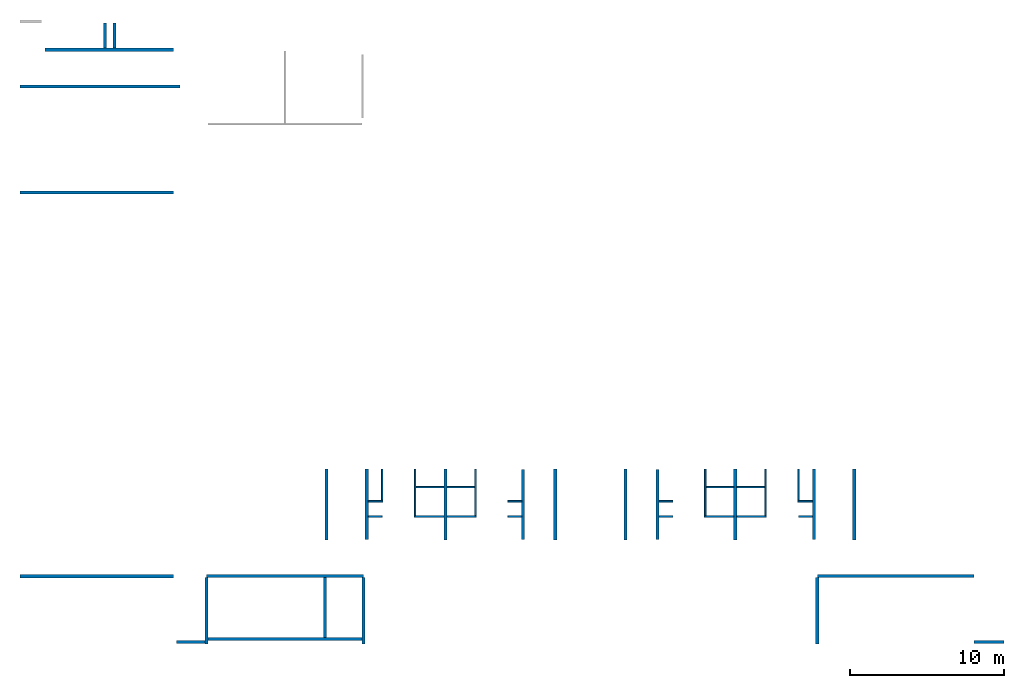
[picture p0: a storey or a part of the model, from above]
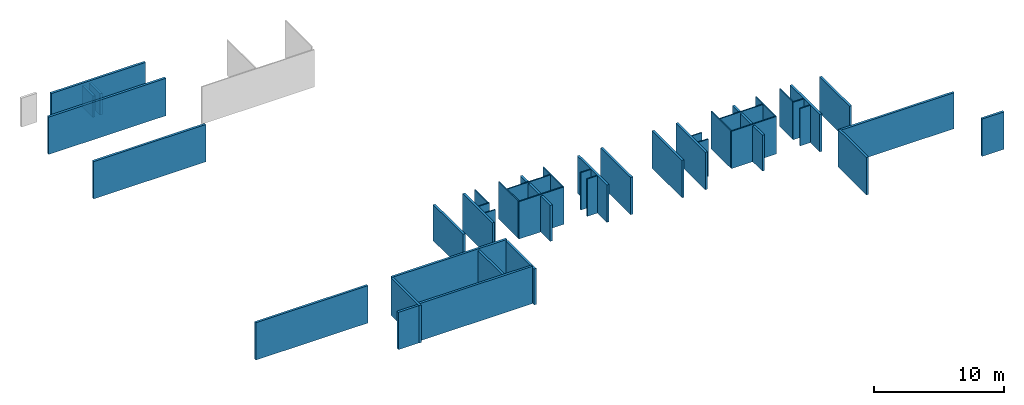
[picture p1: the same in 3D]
Properties of the parts of a building model (IFC2X3), part 1 of 3

# File
Description: ViewDefinition [CoordinationView_V2.0]
File name: Project Number
Time: 2020-09-23T12:17:25
Written by: The EXPRESS Data Manager Version 5.02.0100.07 : 28 Aug 2013
Made in: 21.0.0.383 - Exporter 21.0.0.383 - Alternate UI 21.0.0.383
Comment: STEP Physical File produced by: The EXPRESS Data Manager Version 5.02.0100.07 : 28 Aug 2013 * Module: EDMstepFileFactory/EDMstandAlone * Creation date: Wed Sep 23 12:17:25 2020 * Host: DESKTOP-DG8BND5 * Database: C:\Users\X\AppData\Local\Temp\ed47b6ea-077b-444b-8792-7ce0966b8367\d63a7d49-ede5-44a4-a1c5-d3353abeedfa\ifc * Database version: 5507 * Database creation date: Wed Sep 23 12:11:32 2020 * Schema: IFC2X3 * Model: DataRepository.ifc * Model creation date: Wed Sep 23 12:11:33 2020 * Header model: DataRepository.ifc_HeaderModel * Header model creation date: Wed Sep 23 12:11:33 2020 * EDMuser: sdai-user * EDMgroup: sdai-group * License ID and type: 5605 : Permanent license. Expiry date: * EDMstepFileFactory options: 020000

# IfcProject, Project Number
LongName: Project Name; Phase: Project Status

# IfcSite, Default
RefLatitude: 48, 41, 46, 352233; RefLongitude: 6, 11, 34, 519615; RefElevation: 0 mm
Pset_ProductRequirements - Category: Project Information
Other - Category: Project Information; Client Name: Owner; Project Address: Enter address here; Project Issue Date: Issue Date; Project Name: Project Name; Project Number: Project Number; Project Status: Project Status

# IfcBuilding
Pset_BuildingCommon - NumberOfStoreys: 4
Pset_ProductRequirements - Category: Project Information
Other - Category: Project Information; Client Name: Owner; Project Address: Enter address here; Project Issue Date: Issue Date; Project Name: Project Name; Project Number: Project Number; Project Status: Project Status

# IfcBuildingStorey: Level:Circle Head - Project Datum (4)
Other(Type) - Category: Levels; Family Name: Level
Identity Data(Type) - Type Name: Circle Head - Project Datum
Graphics(Type) - Color: 0; Line Pattern: Centre; Line Weight: 1; Symbol: Anno_Level_Head_Circle: Standard; Symbol at End 1 Default: yes; Symbol at End 2 Default: no
Constraints(Type) - Elevation Base: Project Base Point
Pset_ProductRequirements - Category: Levels
Dimensions - Computation Height: 0 mm
Identity Data - Building Story: yes
Other - Category: Levels; Family: Level: Circle Head - Project Datum; Family and Type: Level: Circle Head - Project Datum; Type: Level: Circle Head - Project Datum; Type Id: Level: Circle Head - Project Datum
Name | LongName = Pset_AirSideSystemInformation, Name = Pset_ProductRequirements, Name = Identity Data, Name | Elevation (mm) = Constraints, Elevation (mm) | Structural
R-1 | R-1 | -3500 | yes
RDC | RDC | 0 | no
R+1 | R+1 | 3660 | no
R+2 | R+2 | 7320 | no

# IfcBuildingElementProxy: Cloisin vitre bois vitrage P-F 3-4H 498x296:Cloisin vitre bois vitrage P-F 3-4H 498x296 (22)
In: RDC
Type - Material: Glass
Type - Constraints - Default Elevation: 0 mm
Type - Identity Data - Type Name: Cloisin vitre bois vitrage P-F 3-4H 498x296
Type - Other - Category: Generic Models; Family Name: Cloisin vitre bois vitrage P-F 3-4H 498x296
Type - Pset_BuildingElementProxyCommon - Reference: Cloisin vitre bois vitrage P-F 3-4H 498x296
Type - Pset_ProductRequirements - Category: Generic Models
Type - Pset_QuantityTakeOff - Reference: Cloisin vitre bois vitrage P-F 3-4H 498x296
Material: Glass, Softwood, Finish Black
Pset_BuildingElementProxyCommon - sets with these values: 2
Constraints - Elevation from Level: 0 mm; Level: Level: RDC; Moves With Nearby Elements: no; Offset from Host: 0 mm; Host: Floor : PlancherChauffant130Rouge
Dimensions - Area: 18.2039 m2; Volume: 0.149386 m3
Other - Family: Cloisin vitre bois vitrage P-F 3-4H 498x296: Cloisin vitre bois vitrage P-F 3-4H 498x296; Family and Type: Cloisin vitre bois vitrage P-F 3-4H 498x296: Cloisin vitre bois vitrage P-F 3-4H 498x296; Type: Cloisin vitre bois vitrage P-F 3-4H 498x296: Cloisin vitre bois vitrage P-F 3-4H 498x296; Type Id: Cloisin vitre bois vitrage P-F 3-4H 498x296: Cloisin vitre bois vitrage P-F 3-4H 498x296
Phasing - Phase Created: Existing
Name (Cloisin vitre bois vitrage P-F 3-4H 498x296:Cloisin vitre bois vitrage P-F 3-4H 498x296:...)
486566 | Pset_ProvisionForVoid - Width: 30 mm; Height: 1830 mm; Depth: 30 mm
486831
486865
486875
486885
486895
486905
486915
486925
486935
486945
486983 | Pset_ProvisionForVoid - Width: 30 mm; Height: 1830 mm; Depth: 30 mm
486985
486987
486989
486991
486993
486995
486997
486999
487001
487003

# IfcBuildingElementProxy: FENETRE.dwg:Fenetre ext 296+70 (124)
Type - Material: PVC, Flexible
Type - Constraints - Default Elevation: 0 mm
Type - Dimensions - Facadecover top: 700 mm
Type - Identity Data - Type Name: Fenetre ext 296+70
Type - Other - Category: Generic Models; Family Name: FENETRE.dwg
Type - Pset_BuildingElementProxyCommon - Reference: Fenetre ext 296+70
Type - Pset_ProductRequirements - Category: Generic Models
Type - Pset_QuantityTakeOff - Reference: Fenetre ext 296+70
Material: PVC, Flexible, Glass
Pset_BuildingElementProxyCommon - sets with these values: 2
Constraints - Elevation from Level: 0 mm; Moves With Nearby Elements: no; Offset from Host: 0 mm
Dimensions - Area: 13.0772 m2; Volume: 0.605172 m3
Other - Family: FENETRE.dwg: Fenetre ext 296+70; Family and Type: FENETRE.dwg: Fenetre ext 296+70; Type: FENETRE.dwg: Fenetre ext 296+70; Type Id: FENETRE.dwg: Fenetre ext 296+70
Phasing - Phase Created: Existing
Name (FENETRE.dwg:Fenetre ext 296+70:...) | In | Host | Level | Group
481956 | RDC | Level : RDC | Level: RDC | Model Group:Array Group 5:484323 | Pset_ProvisionForVoid - Width: 50 mm; Height: 1335 mm; Depth: 50 mm
484326 | RDC | Level : RDC | Level: RDC | Model Group:Array Group 5:484327
484344 | RDC | Level : RDC | Level: RDC | Model Group:Array Group 5:484345
484347 | RDC | Level : RDC | Level: RDC | Model Group:Array Group 5:484348
484350 | RDC | Level : RDC | Level: RDC | Model Group:Array Group 5:484351
484353 | RDC | Level : RDC | Level: RDC | Model Group:Array Group 5:484354
484356 | RDC | Level : RDC | Level: RDC | Model Group:Array Group 5:484357
484359 | RDC | Level : RDC | Level: RDC | Model Group:Array Group 5:484360
484362 | RDC | Level : RDC | Level: RDC | Model Group:Array Group 5:484363
484365 | RDC | Level : RDC | Level: RDC | Model Group:Array Group 5:484366
484368 | RDC | Level : RDC | Level: RDC | Model Group:Array Group 5:484369
484371 | RDC | Level : RDC | Level: RDC | Model Group:Array Group 5:484372
484374 | RDC | Level : RDC | Level: RDC | Model Group:Array Group 5:484375
484377 | RDC | Level : RDC | Level: RDC | Model Group:Array Group 5:484378
484380 | RDC | Level : RDC | Level: RDC | Model Group:Array Group 5:484381
484383 | RDC | Level : RDC | Level: RDC | Model Group:Array Group 5:484384
484386 | RDC | Level : RDC | Level: RDC | Model Group:Array Group 5:484387
484389 | R+1 | Level : R+1 | Level: R+1 | Model Group:Array Group 5:484390
484391 | R+1 | Level : R+1 | Level: R+1 | Model Group:Array Group 5:484392
484393 | R+1 | Level : R+1 | Level: R+1 | Model Group:Array Group 5:484394
484395 | R+1 | Level : R+1 | Level: R+1 | Model Group:Array Group 5:484396
484397 | R+1 | Level : R+1 | Level: R+1 | Model Group:Array Group 5:484398
484399 | R+1 | Level : R+1 | Level: R+1 | Model Group:Array Group 5:484400
484401 | R+1 | Level : R+1 | Level: R+1 | Model Group:Array Group 5:484402
484403 | R+1 | Level : R+1 | Level: R+1 | Model Group:Array Group 5:484404
484405 | R+1 | Level : R+1 | Level: R+1 | Model Group:Array Group 5:484406
484407 | R+1 | Level : R+1 | Level: R+1 | Model Group:Array Group 5:484408
484409 | R+1 | Level : R+1 | Level: R+1 | Model Group:Array Group 5:484410
484411 | R+1 | Level : R+1 | Level: R+1 | Model Group:Array Group 5:484412
484413 | R+1 | Level : R+1 | Level: R+1 | Model Group:Array Group 5:484414
484415 | R+1 | Level : R+1 | Level: R+1 | Model Group:Array Group 5:484416
484417 | R+1 | Level : R+1 | Level: R+1 | Model Group:Array Group 5:484418
484419 | R+1 | Level : R+1 | Level: R+1 | Model Group:Array Group 5:484420
484421 | R+1 | Level : R+1 | Level: R+1 | Model Group:Array Group 5:484422
484424 | R+1 | Level : R+1 | Level: R+1 | Model Group:Array Group 5:484425 | Pset_ProvisionForVoid - Width: 50 mm; Height: 1335 mm; Depth: 50 mm
484426 | R+1 | Level : R+1 | Level: R+1 | Model Group:Array Group 5:484427
484428 | R+1 | Level : R+1 | Level: R+1 | Model Group:Array Group 5:484429
484430 | R+1 | Level : R+1 | Level: R+1 | Model Group:Array Group 5:484431
484432 | R+1 | Level : R+1 | Level: R+1 | Model Group:Array Group 5:484433
484434 | R+1 | Level : R+1 | Level: R+1 | Model Group:Array Group 5:484435
484436 | R+1 | Level : R+1 | Level: R+1 | Model Group:Array Group 5:484437
484438 | R+1 | Level : R+1 | Level: R+1 | Model Group:Array Group 5:484439
484440 | R+1 | Level : R+1 | Level: R+1 | Model Group:Array Group 5:484441
484442 | R+1 | Level : R+1 | Level: R+1 | Model Group:Array Group 5:484443
484444 | R+1 | Level : R+1 | Level: R+1 | Model Group:Array Group 5:484445
484446 | R+1 | Level : R+1 | Level: R+1 | Model Group:Array Group 5:484447
484448 | R+1 | Level : R+1 | Level: R+1 | Model Group:Array Group 5:484449
484450 | R+1 | Level : R+1 | Level: R+1 | Model Group:Array Group 5:484451
484466 | R+1 | Level : R+1 | Level: R+1 | Model Group:Array Group 5:484467
484468 | R+1 | Level : R+1 | Level: R+1 | Model Group:Array Group 5:484469
484470 | R+1 | Level : R+1 | Level: R+1 | Model Group:Array Group 5:484471
484472 | R+1 | Level : R+1 | Level: R+1 | Model Group:Array Group 5:484473
484474 | R+1 | Level : R+1 | Level: R+1 | Model Group:Array Group 5:484475
484476 | R+1 | Level : R+1 | Level: R+1 | Model Group:Array Group 5:484477
484478 | R+1 | Level : R+1 | Level: R+1 | Model Group:Array Group 5:484479
484480 | R+1 | Level : R+1 | Level: R+1 | Model Group:Array Group 5:484481
484482 | R+1 | Level : R+1 | Level: R+1 | Model Group:Array Group 5:484483
484484 | R+1 | Level : R+1 | Level: R+1 | Model Group:Array Group 5:484485
484486 | R+1 | Level : R+1 | Level: R+1 | Model Group:Array Group 5:484487
484488 | R+1 | Level : R+1 | Level: R+1 | Model Group:Array Group 5:484489
484490 | R+1 | Level : R+1 | Level: R+1 | Model Group:Array Group 5:484491
484492 | R+1 | Level : R+1 | Level: R+1 | Model Group:Array Group 5:484493
484519 | RDC | Level : RDC | Level: RDC | Model Group:Array Group 5:484520
484521 | RDC | Level : RDC | Level: RDC | Model Group:Array Group 5:484522
484523 | RDC | Level : RDC | Level: RDC | Model Group:Array Group 5:484524
484525 | RDC | Level : RDC | Level: RDC | Model Group:Array Group 5:484526
484527 | RDC | Level : RDC | Level: RDC | Model Group:Array Group 5:484528
484529 | RDC | Level : RDC | Level: RDC | Model Group:Array Group 5:484530
484531 | RDC | Level : RDC | Level: RDC | Model Group:Array Group 5:484532
484533 | RDC | Level : RDC | Level: RDC | Model Group:Array Group 5:484534
484535 | RDC | Level : RDC | Level: RDC | Model Group:Array Group 5:484536
484537 | RDC | Level : RDC | Level: RDC | Model Group:Array Group 5:484538
484539 | RDC | Level : RDC | Level: RDC | Model Group:Array Group 5:484540
484541 | RDC | Level : RDC | Level: RDC | Model Group:Array Group 5:484542
484543 | RDC | Level : RDC | Level: RDC | Model Group:Array Group 5:484544
484545 | RDC | Level : RDC | Level: RDC | Model Group:Array Group 5:484546
484547 | RDC | Level : RDC | Level: RDC | Model Group:Array Group 5:484548
484549 | RDC | Level : RDC | Level: RDC | Model Group:Array Group 5:484550
484551 | RDC | Level : RDC | Level: RDC | Model Group:Array Group 5:484552
484553 | R+1 | Level : R+1 | Level: R+1
484555 | R+1 | Level : R+1 | Level: R+1 | Model Group:Array Group 5:484556
484557 | R+1 | Level : R+1 | Level: R+1 | Model Group:Array Group 5:484558
484559 | R+1 | Level : R+1 | Level: R+1 | Model Group:Array Group 5:484560
484561 | R+1 | Level : R+1 | Level: R+1 | Model Group:Array Group 5:484562
484563 | R+1 | Level : R+1 | Level: R+1 | Model Group:Array Group 5:484564
484565 | R+1 | Level : R+1 | Level: R+1 | Model Group:Array Group 5:484566
484567 | R+1 | Level : R+1 | Level: R+1 | Model Group:Array Group 5:484568
484569 | R+1 | Level : R+1 | Level: R+1 | Model Group:Array Group 5:484570
484571 | R+1 | Level : R+1 | Level: R+1 | Model Group:Array Group 5:484572
484573 | R+1 | Level : R+1 | Level: R+1 | Model Group:Array Group 5:484574
484575 | R+1 | Level : R+1 | Level: R+1 | Model Group:Array Group 5:484576
484577 | R+1 | Level : R+1 | Level: R+1 | Model Group:Array Group 5:484578
484579 | R+1 | Level : R+1 | Level: R+1 | Model Group:Array Group 5:484580
484581 | R+1 | Level : R+1 | Level: R+1 | Model Group:Array Group 5:484582
484583 | R+1 | Level : R+1 | Level: R+1 | Model Group:Array Group 5:484584
484585 | R+1 | Level : R+1 | Level: R+1 | Model Group:Array Group 5:484586
484587 | R+1 | Level : R+1 | Level: R+1 | Model Group:Array Group 5:484588
484589 | R+1 | Level : R+1 | Level: R+1 | Model Group:Array Group 5:484590
484591 | R+1 | Level : R+1 | Level: R+1 | Model Group:Array Group 5:484592
484593 | R+1 | Level : R+1 | Level: R+1 | Model Group:Array Group 5:484594
484595 | R+1 | Level : R+1 | Level: R+1 | Model Group:Array Group 5:484596
484597 | R+1 | Level : R+1 | Level: R+1 | Model Group:Array Group 5:484598
484599 | R+1 | Level : R+1 | Level: R+1 | Model Group:Array Group 5:484600
484601 | R+1 | Level : R+1 | Level: R+1 | Model Group:Array Group 5:484602
484603 | R+1 | Level : R+1 | Level: R+1 | Model Group:Array Group 5:484604
484605 | R+1 | Level : R+1 | Level: R+1 | Model Group:Array Group 5:484606
484607 | R+1 | Level : R+1 | Level: R+1 | Model Group:Array Group 5:484608
484609 | R+1 | Level : R+1 | Level: R+1 | Model Group:Array Group 5:484610
484611 | R+1 | Level : R+1 | Level: R+1 | Model Group:Array Group 5:484612
484613 | R+1 | Level : R+1 | Level: R+1 | Model Group:Array Group 5:484614
484615 | R+1 | Level : R+1 | Level: R+1 | Model Group:Array Group 5:484616
484617 | R+1 | Level : R+1 | Level: R+1 | Model Group:Array Group 5:484618
484619 | R+1 | Level : R+1 | Level: R+1 | Model Group:Array Group 5:484620
484621 | R+1 | Level : R+1 | Level: R+1 | Model Group:Array Group 5:484622
484623 | R+1 | Level : R+1 | Level: R+1 | Model Group:Array Group 5:484624
484625 | R+1 | Level : R+1 | Level: R+1 | Model Group:Array Group 5:484626
484627 | R+1 | Level : R+1 | Level: R+1 | Model Group:Array Group 5:484628
484629 | R+1 | Level : R+1 | Level: R+1 | Model Group:Array Group 5:484630
484631 | R+1 | Level : R+1 | Level: R+1 | Model Group:Array Group 5:484632
484633 | R+1 | Level : R+1 | Level: R+1 | Model Group:Array Group 5:484634
484635 | R+1 | Level : R+1 | Level: R+1 | Model Group:Array Group 5:484636
484637 | R+1 | Level : R+1 | Level: R+1 | Model Group:Array Group 5:484638
484639 | R+1 | Level : R+1 | Level: R+1 | Model Group:Array Group 5:484640
484641 | R+1 | Level : R+1 | Level: R+1 | Model Group:Array Group 5:484642

# IfcBuildingElementProxy: FENETRE.dwg:Fenetre ext 296+95 (90)
In: R+2
Type - Material: PVC, Flexible
Type - Constraints - Default Elevation: 0 mm
Type - Dimensions - Facadecover top: 950 mm
Type - Identity Data - Type Name: Fenetre ext 296+95
Type - Other - Category: Generic Models; Family Name: FENETRE.dwg
Type - Pset_BuildingElementProxyCommon - Reference: Fenetre ext 296+95
Type - Pset_ProductRequirements - Category: Generic Models
Type - Pset_QuantityTakeOff - Reference: Fenetre ext 296+95
Material: PVC, Flexible, Glass
Pset_BuildingElementProxyCommon - sets with these values: 2
Constraints - Elevation from Level: 0 mm; Moves With Nearby Elements: no; Offset from Host: 0 mm; Level: Level: R+2
Dimensions - Area: 13.5628 m2; Volume: 0.656641 m3
Other - Family: FENETRE.dwg: Fenetre ext 296+95; Family and Type: FENETRE.dwg: Fenetre ext 296+95; Type: FENETRE.dwg: Fenetre ext 296+95; Type Id: FENETRE.dwg: Fenetre ext 296+95
Phasing - Phase Created: Existing
Name (FENETRE.dwg:Fenetre ext 296+95:...) | Host | Group
484697 | Floor : PlancherChauffant130Blue | Model Group:Array Group 6:484793 | Pset_ProvisionForVoid - Width: 50 mm; Height: 1335 mm; Depth: 50 mm
484803 | Level : R+2 | Model Group:Array Group 6:484804
484839 | Level : R+2 | Model Group:Array Group 6:484840
484849 | Level : R+2 | Model Group:Array Group 6:484850
484859 | Level : R+2 | Model Group:Array Group 6:484860
484869 | Level : R+2 | Model Group:Array Group 6:484870
484879 | Level : R+2 | Model Group:Array Group 6:484880
484889 | Level : R+2 | Model Group:Array Group 6:484890
484899 | Level : R+2 | Model Group:Array Group 6:484900
484909 | Level : R+2 | Model Group:Array Group 6:484910
484919 | Level : R+2 | Model Group:Array Group 6:484920
484929 | Level : R+2 | Model Group:Array Group 6:484930
484939 | Level : R+2 | Model Group:Array Group 6:484940
484949 | Level : R+2 | Model Group:Array Group 6:484950
484959 | Level : R+2 | Model Group:Array Group 6:484960
484969 | Level : R+2 | Model Group:Array Group 6:484970
484979 | Level : R+2 | Model Group:Array Group 6:484980
484989 | Level : R+2 | Model Group:Array Group 6:484990 | Pset_ProvisionForVoid - Width: 50 mm; Height: 1335 mm; Depth: 50 mm
484991 | Level : R+2 | Model Group:Array Group 6:484992
484993 | Level : R+2 | Model Group:Array Group 6:484994
484995 | Level : R+2 | Model Group:Array Group 6:484996
484997 | Level : R+2 | Model Group:Array Group 6:484998
484999 | Level : R+2 | Model Group:Array Group 6:485000
485001 | Level : R+2 | Model Group:Array Group 6:485002
485003 | Level : R+2 | Model Group:Array Group 6:485004
485005 | Level : R+2 | Model Group:Array Group 6:485006
485007 | Level : R+2 | Model Group:Array Group 6:485008
485009 | Level : R+2 | Model Group:Array Group 6:485010
485011 | Level : R+2 | Model Group:Array Group 6:485012
485013 | Level : R+2 | Model Group:Array Group 6:485014
485015 | Level : R+2 | Model Group:Array Group 6:485016
485048 | Level : R+2 | Model Group:Array Group 6:485049
485050 | Level : R+2 | Model Group:Array Group 6:485051
485052 | Level : R+2 | Model Group:Array Group 6:485053
485054 | Level : R+2 | Model Group:Array Group 6:485055
485056 | Level : R+2 | Model Group:Array Group 6:485057
485058 | Level : R+2 | Model Group:Array Group 6:485059
485060 | Level : R+2 | Model Group:Array Group 6:485061
485062 | Level : R+2 | Model Group:Array Group 6:485063
485064 | Level : R+2 | Model Group:Array Group 6:485065
485066 | Level : R+2 | Model Group:Array Group 6:485067
485068 | Level : R+2 | Model Group:Array Group 6:485069
485070 | Level : R+2 | Model Group:Array Group 6:485071
485072 | Level : R+2 | Model Group:Array Group 6:485073
485074 | Level : R+2 | Model Group:Array Group 6:485075
485107 | Level : R+2
485109 | Level : R+2 | Model Group:Array Group 6:485110
485111 | Level : R+2 | Model Group:Array Group 6:485112
485113 | Level : R+2 | Model Group:Array Group 6:485114
485115 | Level : R+2 | Model Group:Array Group 6:485116
485117 | Level : R+2 | Model Group:Array Group 6:485118
485119 | Level : R+2 | Model Group:Array Group 6:485120
485121 | Level : R+2 | Model Group:Array Group 6:485122
485123 | Level : R+2 | Model Group:Array Group 6:485124
485125 | Level : R+2 | Model Group:Array Group 6:485126
485127 | Level : R+2 | Model Group:Array Group 6:485128
485129 | Level : R+2 | Model Group:Array Group 6:485130
485131 | Level : R+2 | Model Group:Array Group 6:485132
485133 | Level : R+2 | Model Group:Array Group 6:485134
485135 | Level : R+2 | Model Group:Array Group 6:485136
485137 | Level : R+2 | Model Group:Array Group 6:485138
485139 | Level : R+2 | Model Group:Array Group 6:485140
485141 | Level : R+2 | Model Group:Array Group 6:485142
485143 | Level : R+2 | Model Group:Array Group 6:485144
485145 | Level : R+2 | Model Group:Array Group 6:485146
485147 | Level : R+2 | Model Group:Array Group 6:485148
485149 | Level : R+2 | Model Group:Array Group 6:485150
485151 | Level : R+2 | Model Group:Array Group 6:485152
485153 | Level : R+2 | Model Group:Array Group 6:485154
485155 | Level : R+2 | Model Group:Array Group 6:485156
485157 | Level : R+2 | Model Group:Array Group 6:485158
485159 | Level : R+2 | Model Group:Array Group 6:485160
485161 | Level : R+2 | Model Group:Array Group 6:485162
485163 | Level : R+2 | Model Group:Array Group 6:485164
485165 | Level : R+2 | Model Group:Array Group 6:485166
485167 | Level : R+2 | Model Group:Array Group 6:485168
485171 | Level : R+2 | Model Group:Array Group 6:485172
485173 | Level : R+2 | Model Group:Array Group 6:485174
485175 | Level : R+2 | Model Group:Array Group 6:485176
485177 | Level : R+2 | Model Group:Array Group 6:485178
485179 | Level : R+2 | Model Group:Array Group 6:485180
485181 | Level : R+2 | Model Group:Array Group 6:485182
485183 | Level : R+2 | Model Group:Array Group 6:485184
485185 | Level : R+2 | Model Group:Array Group 6:485186
485187 | Level : R+2 | Model Group:Array Group 6:485188
485189 | Level : R+2 | Model Group:Array Group 6:485190
485191 | Level : R+2 | Model Group:Array Group 6:485192
485193 | Level : R+2 | Model Group:Array Group 6:485194
485195 | Level : R+2 | Model Group:Array Group 6:485196
485197 | Level : R+2 | Model Group:Array Group 6:485198

# IfcBuildingElementProxy: Panneaux mediateque:Panneaux mediateque (56)
Type - Material: Concrete, Precast Smooth, Light Grey
Type - Constraints - Default Elevation: 0 mm
Type - Identity Data - Type Name: Panneaux mediateque
Type - Other - Category: Generic Models; Family Name: Panneaux mediateque
Type - Pset_BuildingElementProxyCommon - Reference: Panneaux mediateque
Type - Pset_ProductRequirements - Category: Generic Models
Type - Pset_QuantityTakeOff - Reference: Panneaux mediateque
Pset_BuildingElementProxyCommon - sets with these values: 2
Constraints - Moves With Nearby Elements: no; Elevation from Level: -700 mm; Offset from Host: -700 mm
Dimensions - Area: 5.16695 m2; Volume: 0.912204 m3
Identity Data - Comments: ThisIsExisting
Other - Family: Panneaux mediateque: Panneaux mediateque; Family and Type: Panneaux mediateque: Panneaux mediateque; Type: Panneaux mediateque: Panneaux mediateque; Type Id: Panneaux mediateque: Panneaux mediateque
Phasing - Phase Created: Existing
Name (Panneaux mediateque:Panneaux mediateque:...) | In | Level | Host
558089 | R+1 | Level: R+1 | Level : R+1 | Pset_ProvisionForVoid - Width: 1830 mm; Depth: 1830 mm
558700 | R+1 | Level: R+1 | Level : R+1
558730 | R+1 | Level: R+1 | Level : R+1
558742 | R+1 | Level: R+1 | Level : R+1
558754 | R+1 | Level: R+1 | Level : R+1
558766 | R+1 | Level: R+1 | Level : R+1
558778 | R+1 | Level: R+1 | Level : R+1
558790 | R+1 | Level: R+1 | Level : R+1
558802 | R+1 | Level: R+1 | Level : R+1
558814 | R+1 | Level: R+1 | Level : R+1
558826 | R+1 | Level: R+1 | Level : R+1
558838 | R+1 | Level: R+1 | Level : R+1
558850 | R+1 | Level: R+1 | Level : R+1
558862 | R+1 | Level: R+1 | Level : R+1
558874 | R+2 | Level: R+2 | Level : R+2
558875 | R+2 | Level: R+2 | Level : R+2
558876 | R+2 | Level: R+2 | Level : R+2
558877 | R+2 | Level: R+2 | Level : R+2
558878 | R+2 | Level: R+2 | Level : R+2
558879 | R+2 | Level: R+2 | Level : R+2
558880 | R+2 | Level: R+2 | Level : R+2
558881 | R+2 | Level: R+2 | Level : R+2
558882 | R+2 | Level: R+2 | Level : R+2
558883 | R+2 | Level: R+2 | Level : R+2
558884 | R+2 | Level: R+2 | Level : R+2
558885 | R+2 | Level: R+2 | Level : R+2
558886 | R+2 | Level: R+2 | Level : R+2
558887 | R+2 | Level: R+2 | Level : R+2
558916 | R+1 | Level: R+1 | Floor : PlancherChauffant130Jaune | Pset_ProvisionForVoid - Width: 1830 mm; Depth: 1830 mm
558917 | R+1 | Level: R+1 | Floor : PlancherChauffant130Jaune
558918 | R+1 | Level: R+1 | Floor : PlancherChauffant130Jaune
558919 | R+1 | Level: R+1 | Floor : PlancherChauffant130Jaune
558920 | R+1 | Level: R+1 | Floor : PlancherChauffant130Jaune
558921 | R+1 | Level: R+1 | Floor : PlancherChauffant130Jaune
558922 | R+1 | Level: R+1 | Floor : PlancherChauffant130Jaune
558923 | R+1 | Level: R+1 | Floor : PlancherChauffant130Jaune
558924 | R+1 | Level: R+1 | Floor : PlancherChauffant130Jaune
558925 | R+1 | Level: R+1 | Floor : PlancherChauffant130Jaune
558926 | R+1 | Level: R+1 | Floor : PlancherChauffant130Jaune
558927 | R+1 | Level: R+1 | Floor : PlancherChauffant130Jaune
558928 | R+1 | Level: R+1 | Floor : PlancherChauffant130Jaune
558929 | R+1 | Level: R+1 | Floor : PlancherChauffant130Jaune
558930 | R+2 | Level: R+2 | Floor : PlancherChauffant130Blue
558931 | R+2 | Level: R+2 | Floor : PlancherChauffant130Blue
558932 | R+2 | Level: R+2 | Floor : PlancherChauffant130Blue
558933 | R+2 | Level: R+2 | Floor : PlancherChauffant130Blue
558934 | R+2 | Level: R+2 | Floor : PlancherChauffant130Blue
558935 | R+2 | Level: R+2 | Floor : PlancherChauffant130Blue
558936 | R+2 | Level: R+2 | Floor : PlancherChauffant130Blue
558937 | R+2 | Level: R+2 | Floor : PlancherChauffant130Blue
558938 | R+2 | Level: R+2 | Floor : PlancherChauffant130Blue
558939 | R+2 | Level: R+2 | Floor : PlancherChauffant130Blue
558940 | R+2 | Level: R+2 | Floor : PlancherChauffant130Blue
558941 | R+2 | Level: R+2 | Floor : PlancherChauffant130Blue
558942 | R+2 | Level: R+2 | Floor : PlancherChauffant130Blue
558943 | R+2 | Level: R+2 | Floor : PlancherChauffant130Blue

# IfcBuildingElementProxy: Porte noire:Porte noire (140)
Type - Material: Plywood, Sheathing
Type - Constraints - Default Elevation: 0 mm
Type - Identity Data - Type Name: Porte noire
Type - Other - Category: Generic Models; Family Name: Porte noire
Type - Pset_BuildingElementProxyCommon - Reference: Porte noire
Type - Pset_ProductRequirements - Category: Generic Models
Type - Pset_QuantityTakeOff - Reference: Porte noire
Material: Plywood, Sheathing, Glass
Pset_BuildingElementProxyCommon - sets with these values: 2
Constraints - Elevation from Level: 0 mm; Moves With Nearby Elements: no; Offset from Host: 0 mm
Dimensions - Area: 9.23985 m2; Volume: 0.109856 m3
Identity Data - Comments: ThisIsExisting
Other - Family: Porte noire: Porte noire; Family and Type: Porte noire: Porte noire; Type: Porte noire: Porte noire; Type Id: Porte noire: Porte noire
Phasing - Phase Created: Existing
Name (Porte noire:Porte noire:...) | In | Level | Host
554590 | R+1 | Level: R+1 | Floor : PlancherChauffant130Jaune | Pset_ProvisionForVoid - Width: 1260 mm; Height: 665 mm; Depth: 1260 mm
554633 | R+1 | Level: R+1 | Floor : PlancherChauffant130Jaune
554675 | R+1 | Level: R+1 | Floor : PlancherChauffant130Jaune
554685 | R+1 | Level: R+1 | Floor : PlancherChauffant130Jaune
554695 | R+1 | Level: R+1 | Floor : PlancherChauffant130Jaune
554705 | R+1 | Level: R+1 | Floor : PlancherChauffant130Jaune
554715 | R+1 | Level: R+1 | Floor : PlancherChauffant130Jaune
554725 | R+1 | Level: R+1 | Floor : PlancherChauffant130Jaune
554735 | R+1 | Level: R+1 | Floor : PlancherChauffant130Jaune
554745 | R+1 | Level: R+1 | Floor : PlancherChauffant130Jaune
554755 | R+1 | Level: R+1 | Floor : PlancherChauffant130Jaune
554765 | R+1 | Level: R+1 | Floor : PlancherChauffant130Jaune
554775 | R+1 | Level: R+1 | Floor : PlancherChauffant130Jaune
554785 | R+1 | Level: R+1 | Floor : PlancherChauffant130Jaune
554795 | R+1 | Level: R+1 | Floor : PlancherChauffant130Jaune
554805 | R+1 | Level: R+1 | Floor : PlancherChauffant130Jaune
554815 | R+1 | Level: R+1 | Floor : PlancherChauffant130Jaune
554835 | R+2 | Level: R+2 | Floor : PlancherChauffant130Blue
554836 | R+2 | Level: R+2 | Floor : PlancherChauffant130Blue
554837 | R+2 | Level: R+2 | Floor : PlancherChauffant130Blue
554838 | R+2 | Level: R+2 | Floor : PlancherChauffant130Blue
554839 | R+2 | Level: R+2 | Floor : PlancherChauffant130Blue
554840 | R+2 | Level: R+2 | Floor : PlancherChauffant130Blue
554841 | R+2 | Level: R+2 | Floor : PlancherChauffant130Blue
554842 | R+2 | Level: R+2 | Floor : PlancherChauffant130Blue
554843 | R+2 | Level: R+2 | Floor : PlancherChauffant130Blue
554844 | R+2 | Level: R+2 | Floor : PlancherChauffant130Blue
554845 | R+2 | Level: R+2 | Floor : PlancherChauffant130Blue
554846 | R+2 | Level: R+2 | Floor : PlancherChauffant130Blue
554847 | R+2 | Level: R+2 | Floor : PlancherChauffant130Blue
554848 | R+2 | Level: R+2 | Floor : PlancherChauffant130Blue
554849 | R+2 | Level: R+2 | Floor : PlancherChauffant130Blue
554850 | R+2 | Level: R+2 | Floor : PlancherChauffant130Blue
554851 | R+2 | Level: R+2 | Floor : PlancherChauffant130Blue
554893 | R+1 | Level: R+1 | Level : R+1
554894 | R+1 | Level: R+1 | Level : R+1
554895 | R+1 | Level: R+1 | Level : R+1
554896 | R+1 | Level: R+1 | Level : R+1
554897 | R+1 | Level: R+1 | Level : R+1
554898 | R+1 | Level: R+1 | Level : R+1
554899 | R+1 | Level: R+1 | Level : R+1
554900 | R+1 | Level: R+1 | Level : R+1
554901 | R+1 | Level: R+1 | Level : R+1
554902 | R+1 | Level: R+1 | Level : R+1
554903 | R+1 | Level: R+1 | Level : R+1
554904 | R+1 | Level: R+1 | Level : R+1
554905 | R+1 | Level: R+1 | Level : R+1
554906 | R+1 | Level: R+1 | Level : R+1
554917 | R+2 | Level: R+2 | Level : R+2
554918 | R+2 | Level: R+2 | Level : R+2
554919 | R+2 | Level: R+2 | Level : R+2
554920 | R+2 | Level: R+2 | Level : R+2
554921 | R+2 | Level: R+2 | Level : R+2
554922 | R+2 | Level: R+2 | Level : R+2
554923 | R+2 | Level: R+2 | Level : R+2
554924 | R+2 | Level: R+2 | Level : R+2
554925 | R+2 | Level: R+2 | Level : R+2
554926 | R+2 | Level: R+2 | Level : R+2
554927 | R+2 | Level: R+2 | Level : R+2
554928 | R+2 | Level: R+2 | Level : R+2
554929 | R+2 | Level: R+2 | Level : R+2
554930 | R+2 | Level: R+2 | Level : R+2
554997 | R+1 | Level: R+1 | Floor : PlancherChauffant130Jaune | Pset_ProvisionForVoid - Width: 1260 mm; Height: 2 mm; Depth: 1260 mm
554998 | R+1 | Level: R+1 | Floor : PlancherChauffant130Jaune
554999 | R+1 | Level: R+1 | Floor : PlancherChauffant130Jaune
555000 | R+1 | Level: R+1 | Floor : PlancherChauffant130Jaune
555001 | R+1 | Level: R+1 | Floor : PlancherChauffant130Jaune
555002 | R+1 | Level: R+1 | Floor : PlancherChauffant130Jaune
555003 | R+1 | Level: R+1 | Floor : PlancherChauffant130Jaune
555004 | R+1 | Level: R+1 | Floor : PlancherChauffant130Jaune
555005 | R+1 | Level: R+1 | Floor : PlancherChauffant130Jaune
555006 | R+1 | Level: R+1 | Floor : PlancherChauffant130Jaune
555007 | R+1 | Level: R+1 | Floor : PlancherChauffant130Jaune
555008 | R+1 | Level: R+1 | Floor : PlancherChauffant130Jaune
555009 | R+1 | Level: R+1 | Floor : PlancherChauffant130Jaune
555010 | R+1 | Level: R+1 | Floor : PlancherChauffant130Jaune
555011 | R+1 | Level: R+1 | Floor : PlancherChauffant130Jaune
555012 | R+1 | Level: R+1 | Floor : PlancherChauffant130Jaune
555013 | R+1 | Level: R+1 | Floor : PlancherChauffant130Jaune
555014 | R+2 | Level: R+2 | Floor : PlancherChauffant130Blue
555015 | R+2 | Level: R+2 | Floor : PlancherChauffant130Blue
555016 | R+2 | Level: R+2 | Floor : PlancherChauffant130Blue
555017 | R+2 | Level: R+2 | Floor : PlancherChauffant130Blue
555018 | R+2 | Level: R+2 | Floor : PlancherChauffant130Blue
555019 | R+2 | Level: R+2 | Floor : PlancherChauffant130Blue
555020 | R+2 | Level: R+2 | Floor : PlancherChauffant130Blue
555021 | R+2 | Level: R+2 | Floor : PlancherChauffant130Blue
555022 | R+2 | Level: R+2 | Floor : PlancherChauffant130Blue
555023 | R+2 | Level: R+2 | Floor : PlancherChauffant130Blue
555024 | R+2 | Level: R+2 | Floor : PlancherChauffant130Blue
555025 | R+2 | Level: R+2 | Floor : PlancherChauffant130Blue
555026 | R+2 | Level: R+2 | Floor : PlancherChauffant130Blue
555027 | R+2 | Level: R+2 | Floor : PlancherChauffant130Blue
555028 | R+2 | Level: R+2 | Floor : PlancherChauffant130Blue
555029 | R+2 | Level: R+2 | Floor : PlancherChauffant130Blue
555030 | R+2 | Level: R+2 | Floor : PlancherChauffant130Blue
555031 | R+1 | Level: R+1 | Floor : PlancherChauffant130Jaune
555032 | R+1 | Level: R+1 | Floor : PlancherChauffant130Jaune
555033 | R+1 | Level: R+1 | Floor : PlancherChauffant130Jaune
555034 | R+1 | Level: R+1 | Floor : PlancherChauffant130Jaune
555035 | R+1 | Level: R+1 | Floor : PlancherChauffant130Jaune
555036 | R+1 | Level: R+1 | Floor : PlancherChauffant130Jaune
555037 | R+1 | Level: R+1 | Floor : PlancherChauffant130Jaune
555038 | R+1 | Level: R+1 | Floor : PlancherChauffant130Jaune
555039 | R+1 | Level: R+1 | Floor : PlancherChauffant130Jaune
555040 | R+1 | Level: R+1 | Floor : PlancherChauffant130Jaune
555041 | R+1 | Level: R+1 | Floor : PlancherChauffant130Jaune
555042 | R+1 | Level: R+1 | Floor : PlancherChauffant130Jaune
555043 | R+1 | Level: R+1 | Floor : PlancherChauffant130Jaune
555044 | R+1 | Level: R+1 | Floor : PlancherChauffant130Jaune
555045 | R+2 | Level: R+2 | Floor : PlancherChauffant130Blue
555046 | R+2 | Level: R+2 | Floor : PlancherChauffant130Blue
555047 | R+2 | Level: R+2 | Floor : PlancherChauffant130Blue
555048 | R+2 | Level: R+2 | Floor : PlancherChauffant130Blue
555049 | R+2 | Level: R+2 | Floor : PlancherChauffant130Blue
555050 | R+2 | Level: R+2 | Floor : PlancherChauffant130Blue
555051 | R+2 | Level: R+2 | Floor : PlancherChauffant130Blue
555052 | R+2 | Level: R+2 | Floor : PlancherChauffant130Blue
555053 | R+2 | Level: R+2 | Floor : PlancherChauffant130Blue
555054 | R+2 | Level: R+2 | Floor : PlancherChauffant130Blue
555055 | R+2 | Level: R+2 | Floor : PlancherChauffant130Blue
555056 | R+2 | Level: R+2 | Floor : PlancherChauffant130Blue
555057 | R+2 | Level: R+2 | Floor : PlancherChauffant130Blue
555058 | R+2 | Level: R+2 | Floor : PlancherChauffant130Blue
555069 | RDC | Level: RDC | Level : RDC
555596 | RDC | Level: RDC | Level : RDC
555609 | RDC | Level: RDC | Level : RDC
555621 | RDC | Level: RDC | Level : RDC
555633 | RDC | Level: RDC | Level : RDC
555645 | RDC | Level: RDC | Level : RDC
555657 | RDC | Level: RDC | Level : RDC
555673 | RDC | Level: RDC | Level : RDC
577232 | RDC | Level: RDC | Level : RDC
577289 | RDC | Level: RDC | Level : RDC
577305 | RDC | Level: RDC | Level : RDC
577321 | RDC | Level: RDC | Level : RDC
577331 | RDC | Level: RDC | Level : RDC
577332 | RDC | Level: RDC | Level : RDC
577333 | RDC | Level: RDC | Level : RDC
577334 | RDC | Level: RDC | Level : RDC

# IfcCurtainWall: Curtain Wall:Curtain_Wall-Empty (7)
In: RDC
Type - Construction - Function: Exterior; Automatically Embed: yes; Join Condition: Not Defined
Type - Horizontal Grid - Adjust for Mullion Size: no; Spacing: 1500 mm
Type - Horizontal Mullions - Border 1 Type: Rectangular Mullion: 50x150mm; Border 2 Type: Rectangular Mullion: 50x150mm
Type - Identity Data - Keynote: H11; Type Name: Curtain_Wall-Empty
Type - Other - Category: Walls; Family Name: Curtain Wall
Type - Vertical Grid - Adjust for Mullion Size: yes; Layout: Fixed Distance; Spacing: 2260 mm
Type - Vertical Mullions - Border 1 Type: Rectangular Mullion: 50x150mm; Border 2 Type: Rectangular Mullion: 50x150mm; Interior Type: Rectangular Mullion: 50x150mm
Type - Pset_CurtainWallCommon - IsExternal: no; Reference: Curtain_Wall-Empty
Type - Pset_ProductRequirements - Category: Walls
Type - Pset_QuantityTakeOff - Reference: Curtain_Wall-Empty
Pset_CurtainWallCommon - IsExternal: yes
Constraints - Base is Attached: no; Base Offset: 0 mm; Cross-Section: Vertical; Related to Mass: no; Room Bounding: yes; Top is Attached: no; Base Constraint: Level: RDC; Top Constraint: Level: R+1
Horizontal Grid - Angle: 0 deg; Justification: Beginning; Offset: 0 mm
Identity Data - Comments: ThisIsExisting
Other - Family: Curtain Wall: Curtain_Wall-Empty; Family and Type: Curtain Wall: Curtain_Wall-Empty; Type: Curtain Wall: Curtain_Wall-Empty; Type Id: Curtain Wall: Curtain_Wall-Empty
Phasing - Phase Created: Existing
Structural - Enable Analytical Model: no; Structural: no; Structural Usage: Non-bearing
Name (Curtain Wall:Curtain_Wall-Empty:...) | Top Offset (mm) | Unconnected Height (mm) | Area (m2) | Length (mm) | Horizontal Grid, Number | Angle (deg) = Offset (mm) | Justification | Vertical Grid, Number
575831 | 0 | 3660 | 29.7192 | 8335 | 2 | 0 | Beginning | 3
576403 | 0 | 3660 | 29.7192 | 8335 | 2 | 0 | Beginning | 3
576491 | 0 | 3660 | 36.417 | 9950 | 2 | 0 | Beginning | 4
576824 | -700 | 2960 | 29.452 | 9950 | 2 | 0 | Beginning | 4
576992 | 0 | 3660 | 36.4243 | 9952 | 4 | Horizontal Grid - sets with these values: 2
577151 | 0 | 3660 | 36.4243 | 9952 | 4 | Horizontal Grid - sets with these values: 2
577865 | 0 | 3660 | 16.0381 | 4382 | 4 | 0 | Beginning | 1

# IfcCurtainWall: Curtain Wall:Curtain_Wall-Empty 2 (2)
In: RDC
Type - Construction - Function: Exterior; Automatically Embed: yes; Join Condition: Not Defined
Type - Horizontal Grid - Adjust for Mullion Size: no; Spacing: 1500 mm
Type - Horizontal Mullions - Border 1 Type: Rectangular Mullion: 50x150mm; Border 2 Type: Rectangular Mullion: 50x150mm
Type - Identity Data - Keynote: H11; Type Name: Curtain_Wall-Empty 2
Type - Other - Category: Walls; Family Name: Curtain Wall
Type - Vertical Grid - Adjust for Mullion Size: yes; Layout: Fixed Distance; Spacing: 2260 mm
Type - Vertical Mullions - Border 1 Type: Rectangular Mullion: 50x150mm; Border 2 Type: Rectangular Mullion: 50x150mm; Interior Type: Rectangular Mullion: 50x150mm
Type - Pset_CurtainWallCommon - IsExternal: no; Reference: Curtain_Wall-Empty 2
Type - Pset_ProductRequirements - Category: Walls
Type - Pset_QuantityTakeOff - Reference: Curtain_Wall-Empty 2
Pset_CurtainWallCommon - IsExternal: yes
Constraints - Base is Attached: no; Base Offset: 0 mm; Cross-Section: Vertical; Related to Mass: no; Room Bounding: yes; Top is Attached: no; Top Offset: 0 mm; Base Constraint: Level: RDC; Top Constraint: Level: R+1; Unconnected Height: 3660 mm
Dimensions - Area: 36.4316 m2; Length: 9954 mm
Horizontal Grid - Angle: 0 deg; Justification: Beginning; Offset: 0 mm; Number: 4; sets with these values: 2
Identity Data - Comments: ThisIsExisting
Other - Family: Curtain Wall: Curtain_Wall-Empty 2; Family and Type: Curtain Wall: Curtain_Wall-Empty 2; Type: Curtain Wall: Curtain_Wall-Empty 2; Type Id: Curtain Wall: Curtain_Wall-Empty 2
Phasing - Phase Created: Existing
Structural - Enable Analytical Model: no; Structural: no; Structural Usage: Non-bearing
Name (Curtain Wall:Curtain_Wall-Empty 2:...)
578327
578457

# IfcCurtainWall: Curtain Wall:Curtain_Wall-Exterior_Glazing (6)
Type - Construction(Type) - Function: Exterior; Automatically Embed: yes; Join Condition: Border and Vertical Grid Continuous
Type - Horizontal Grid(Type) - Adjust for Mullion Size: yes; Layout: Fixed Number; Spacing: 4000 mm
Type - Horizontal Mullions(Type) - Border 1 Type: Rectangular Mullion: 30mm_Square; Border 2 Type: Rectangular Mullion: 30mm_Square; Interior Type: Rectangular Mullion: 30mm_Square
Type - Identity Data(Type) - Keynote: H11; Type Name: Curtain_Wall-Exterior_Glazing
Type - Other(Type) - Category: Walls; Family Name: Curtain Wall
Type - Vertical Grid(Type) - Adjust for Mullion Size: yes; Layout: Fixed Number; Spacing: 1830 mm
Type - Vertical Mullions(Type) - Border 1 Type: Rectangular Mullion: 30mm_Square; Border 2 Type: Rectangular Mullion: 30mm_Square; Interior Type: Rectangular Mullion: 30mm_Square
Type - Pset_CurtainWallCommon - IsExternal: no; Reference: Curtain_Wall-Exterior_Glazing
Type - Pset_ProductRequirements - Category: Walls
Type - Pset_QuantityTakeOff - Reference: Curtain_Wall-Exterior_Glazing
Constraints - Base is Attached: no; Cross-Section: Vertical; Related to Mass: no; Room Bounding: yes; Top is Attached: no
Horizontal Grid - Angle: 0 deg; Justification: Beginning; Offset: 0 mm
Identity Data - Comments: ThisIsExisting
Other - Category: Walls; Family: Curtain Wall: Curtain_Wall-Exterior_Glazing; Family and Type: Curtain Wall: Curtain_Wall-Exterior_Glazing; Type: Curtain Wall: Curtain_Wall-Exterior_Glazing; Type Id: Curtain Wall: Curtain_Wall-Exterior_Glazing
Phasing - Phase Created: Existing
Structural - Enable Analytical Model: no; Structural: no; Structural Usage: Non-bearing
Vertical Grid - Angle: 0 deg; Justification: Beginning; Offset: 0 mm
Name (Curtain Wall:Curtain_Wall-Exterior_Glazing:...) | In | Base Offset (mm) | Top Offset (mm) | Base Constraint | Top Constraint | Unconnected Height (mm) | Area (m2) | Length (mm) | Horizontal Grid, Number | Vertical Grid, Number | Reference | sets with these values
567057 | R+2 | 0 | 0 | Level: R+2 | Level: TOITURE | 3520 | 35.024 | 9950 | 1 | 4 | Pset_CurtainWallCommon - IsExternal: yes
567785 | R+1 | 0 | -140 | Level: R+1 | Level: R+2 | 3520 | 35.024 | 9950 | 1 | 4 | Pset_CurtainWallCommon - IsExternal: yes
567847 | R+2 | 0 | 0 | Level: R+2 | Level: TOITURE | 3520 | 35.024 | 9950 | 1 | 4 | Curtain_Wall-Exterior_Glazing | 2
567890 | R+1 | 0 | -140 | Level: R+1 | Level: R+2 | 3520 | 35.024 | 9950 | 1 | 4 | Curtain_Wall-Exterior_Glazing | 2
569500 | R+1 | -844.27 | -380 | Level: R+1 | Level: TOP | 8034.27 | 36.3149 | 4520 | 7 | 1 | Curtain_Wall-Exterior_Glazing | 2
579475 | R+1 | -844.27 | -380 | Level: R+1 | Level: TOP | 8034.27 | 36.3149 | 4520 | 7 | 1 | Curtain_Wall-Exterior_Glazing | 2

# IfcGroup: Model Group:Array Group 5 (123)
Constraints - Origin Level Offset: 0 mm
Other - Category: Model Groups; Family: Model Group: Array Group 5; Family and Type: Model Group: Array Group 5; Type: Model Group: Array Group 5; Type Id: Model Group: Array Group 5
Other(Type) - Category: Model Groups; Family Name: Model Group
Identity Data(Type) - Type Name: Array Group 5
Name (Model Group:Array Group 5:...) | Reference Level
484323 | Level: RDC
484327 | Level: RDC
484345 | Level: RDC
484348 | Level: RDC
484351 | Level: RDC
484354 | Level: RDC
484357 | Level: RDC
484360 | Level: RDC
484363 | Level: RDC
484366 | Level: RDC
484369 | Level: RDC
484372 | Level: RDC
484375 | Level: RDC
484378 | Level: RDC
484381 | Level: RDC
484384 | Level: RDC
484387 | Level: RDC
484390 | Level: R+1
484392 | Level: R+1
484394 | Level: R+1
484396 | Level: R+1
484398 | Level: R+1
484400 | Level: R+1
484402 | Level: R+1
484404 | Level: R+1
484406 | Level: R+1
484408 | Level: R+1
484410 | Level: R+1
484412 | Level: R+1
484414 | Level: R+1
484416 | Level: R+1
484418 | Level: R+1
484420 | Level: R+1
484422 | Level: R+1
484425 | Level: R+1
484427 | Level: R+1
484429 | Level: R+1
484431 | Level: R+1
484433 | Level: R+1
484435 | Level: R+1
484437 | Level: R+1
484439 | Level: R+1
484441 | Level: R+1
484443 | Level: R+1
484445 | Level: R+1
484447 | Level: R+1
484449 | Level: R+1
484451 | Level: R+1
484467 | Level: R+1
484469 | Level: R+1
484471 | Level: R+1
484473 | Level: R+1
484475 | Level: R+1
484477 | Level: R+1
484479 | Level: R+1
484481 | Level: R+1
484483 | Level: R+1
484485 | Level: R+1
484487 | Level: R+1
484489 | Level: R+1
484491 | Level: R+1
484493 | Level: R+1
484520 | Level: RDC
484522 | Level: RDC
484524 | Level: RDC
484526 | Level: RDC
484528 | Level: RDC
484530 | Level: RDC
484532 | Level: RDC
484534 | Level: RDC
484536 | Level: RDC
484538 | Level: RDC
484540 | Level: RDC
484542 | Level: RDC
484544 | Level: RDC
484546 | Level: RDC
484548 | Level: RDC
484550 | Level: RDC
484552 | Level: RDC
484556 | Level: R+1
484558 | Level: R+1
484560 | Level: R+1
484562 | Level: R+1
484564 | Level: R+1
484566 | Level: R+1
484568 | Level: R+1
484570 | Level: R+1
484572 | Level: R+1
484574 | Level: R+1
484576 | Level: R+1
484578 | Level: R+1
484580 | Level: R+1
484582 | Level: R+1
484584 | Level: R+1
484586 | Level: R+1
484588 | Level: R+1
484590 | Level: R+1
484592 | Level: R+1
484594 | Level: R+1
484596 | Level: R+1
484598 | Level: R+1
484600 | Level: R+1
484602 | Level: R+1
484604 | Level: R+1
484606 | Level: R+1
484608 | Level: R+1
484610 | Level: R+1
484612 | Level: R+1
484614 | Level: R+1
484616 | Level: R+1
484618 | Level: R+1
484620 | Level: R+1
484622 | Level: R+1
484624 | Level: R+1
484626 | Level: R+1
484628 | Level: R+1
484630 | Level: R+1
484632 | Level: R+1
484634 | Level: R+1
484636 | Level: R+1
484638 | Level: R+1
484640 | Level: R+1
484642 | Level: R+1

# IfcGroup: Model Group:Array Group 6 (89)
Constraints - Origin Level Offset: 0 mm; Reference Level: Level: R+2
Other - Category: Model Groups; Family: Model Group: Array Group 6; Family and Type: Model Group: Array Group 6; Type: Model Group: Array Group 6; Type Id: Model Group: Array Group 6
Other(Type) - Category: Model Groups; Family Name: Model Group
Identity Data(Type) - Type Name: Array Group 6
Name (Model Group:Array Group 6:...)
484793
484804
484840
484850
484860
484870
484880
484890
484900
484910
484920
484930
484940
484950
484960
484970
484980
484990
484992
484994
484996
484998
485000
485002
485004
485006
485008
485010
485012
485014
485016
485049
485051
485053
485055
485057
485059
485061
485063
485065
485067
485069
485071
485073
485075
485110
485112
485114
485116
485118
485120
485122
485124
485126
485128
485130
485132
485134
485136
485138
485140
485142
485144
485146
485148
485150
485152
485154
485156
485158
485160
485162
485164
485166
485168
485172
485174
485176
485178
485180
485182
485184
485186
485188
485190
485192
485194
485196
485198

# IfcMember: Rectangular Mullion:30mm_Square (192)
Type - PredefinedType: MULLION; Material: Aluminium
Type - Constraints - Angle: 0 deg; Offset: 0 mm
Type - Construction - Corner Mullion: no; Position: Perpendicular to Face; Thickness: 30 mm
Type - Dimensions - Width on side 1: 15 mm; Width on side 2: 15 mm
Type - Identity Data - Keynote: H11; Type Name: 30mm_Square
Type - Materials and Finishes - Material: Aluminium
Type - Other - Category: Curtain Wall Mullions; Family Name: Rectangular Mullion
Type - Pset_MemberCommon - IsExternal: no; Reference: 30mm_Square
Type - Pset_ProductRequirements - Category: Curtain Wall Mullions
Type - Pset_QuantityTakeOff - Reference: 30mm_Square
Other - Family: Rectangular Mullion: 30mm_Square; Family and Type: Rectangular Mullion: 30mm_Square; Host Id: Curtain Wall: Curtain_Wall-Exterior_Glazing; Type: Rectangular Mullion: 30mm_Square; Type Id: Rectangular Mullion: 30mm_Square
Phasing - Phase Created: Existing
Pset_MemberCommon - IsExternal: yes
Name (Rectangular Mullion:30mm_Square:...) | In | Level | Area (m2) | Length (mm) = Span (mm) | Volume (m3)
567380 | R+2 | Level: R+2 | 0.12084 | 1999 | 0.0017991
567381 | R+2 | Level: R+2 | 0.12084 | 1999 | 0.0017991
567382 | R+2 | Level: R+2 | 0.11994 | 1984 | 0.0017856
567383 | R+2 | Level: R+2 | 0.11994 | 1984 | 0.0017856
567384 | R+2 | Level: R+2 | 0.11994 | 1984 | 0.0017856
567385 | R+2 | Level: R+2 | 0.12084 | 1999 | 0.0017991
567386 | R+2 | Level: R+2 | 0.11994 | 1984 | 0.0017856
567387 | R+2 | Level: R+2 | 0.11994 | 1984 | 0.0017856
567388 | R+2 | Level: R+2 | 0.11994 | 1984 | 0.0017856
567389 | R+2 | Level: R+2 | 0.12084 | 1999 | 0.0017991
567390 | R+2 | Level: R+2 | 0.11814 | 1954 | 0.0017586
567391 | R+2 | Level: R+2 | 0.11814 | 1954 | 0.0017586
567392 | R+2 | Level: R+2 | 0.11814 | 1954 | 0.0017586
567393 | R+2 | Level: R+2 | 0.11814 | 1954 | 0.0017586
567394 | R+2 | Level: R+2 | 0.11814 | 1954 | 0.0017586
567534 | R+2 | Level: R+2 | 0.1047 | 1730 | 0.001557
567535 | R+2 | Level: R+2 | 0.1047 | 1730 | 0.001557
567536 | R+2 | Level: R+2 | 0.1047 | 1730 | 0.001557
567537 | R+2 | Level: R+2 | 0.1047 | 1730 | 0.001557
567685 | R+2 | Level: R+2 | 0.1047 | 1730 | 0.001557
567686 | R+2 | Level: R+2 | 0.1047 | 1730 | 0.001557
567687 | R+2 | Level: R+2 | 0.1047 | 1730 | 0.001557
567688 | R+2 | Level: R+2 | 0.1047 | 1730 | 0.001557
567689 | R+2 | Level: R+2 | 0.1047 | 1730 | 0.001557
567690 | R+2 | Level: R+2 | 0.1047 | 1730 | 0.001557
567691 | R+2 | Level: R+2 | 0.1047 | 1730 | 0.001557
567692 | R+2 | Level: R+2 | 0.1047 | 1730 | 0.001557
567801 | R+1 | Level: R+1 | 0.12084 | 1999 | 0.0017991
567802 | R+1 | Level: R+1 | 0.12084 | 1999 | 0.0017991
567803 | R+1 | Level: R+1 | 0.11994 | 1984 | 0.0017856
567804 | R+1 | Level: R+1 | 0.11994 | 1984 | 0.0017856
567805 | R+1 | Level: R+1 | 0.11994 | 1984 | 0.0017856
567806 | R+1 | Level: R+1 | 0.12084 | 1999 | 0.0017991
567807 | R+1 | Level: R+1 | 0.11994 | 1984 | 0.0017856
567808 | R+1 | Level: R+1 | 0.11994 | 1984 | 0.0017856
567809 | R+1 | Level: R+1 | 0.11994 | 1984 | 0.0017856
567810 | R+1 | Level: R+1 | 0.12084 | 1999 | 0.0017991
567811 | R+1 | Level: R+1 | 0.11814 | 1954 | 0.0017586
567812 | R+1 | Level: R+1 | 0.11814 | 1954 | 0.0017586
567813 | R+1 | Level: R+1 | 0.11814 | 1954 | 0.0017586
567814 | R+1 | Level: R+1 | 0.11814 | 1954 | 0.0017586
567815 | R+1 | Level: R+1 | 0.11814 | 1954 | 0.0017586
567816 | R+1 | Level: R+1 | 0.1047 | 1730 | 0.001557
567817 | R+1 | Level: R+1 | 0.1047 | 1730 | 0.001557
567818 | R+1 | Level: R+1 | 0.1047 | 1730 | 0.001557
567819 | R+1 | Level: R+1 | 0.1047 | 1730 | 0.001557
567820 | R+1 | Level: R+1 | 0.1047 | 1730 | 0.001557
567821 | R+1 | Level: R+1 | 0.1047 | 1730 | 0.001557
567822 | R+1 | Level: R+1 | 0.1047 | 1730 | 0.001557
567823 | R+1 | Level: R+1 | 0.1047 | 1730 | 0.001557
567824 | R+1 | Level: R+1 | 0.1047 | 1730 | 0.001557
567825 | R+1 | Level: R+1 | 0.1047 | 1730 | 0.001557
567826 | R+1 | Level: R+1 | 0.1047 | 1730 | 0.001557
567827 | R+1 | Level: R+1 | 0.1047 | 1730 | 0.001557
567863 | R+2 | Level: R+2 | 0.12084 | 1999 | 0.0017991
567864 | R+2 | Level: R+2 | 0.12084 | 1999 | 0.0017991
567865 | R+2 | Level: R+2 | 0.11994 | 1984 | 0.0017856
567866 | R+2 | Level: R+2 | 0.11994 | 1984 | 0.0017856
567867 | R+2 | Level: R+2 | 0.11994 | 1984 | 0.0017856
567868 | R+2 | Level: R+2 | 0.12084 | 1999 | 0.0017991
567869 | R+2 | Level: R+2 | 0.11994 | 1984 | 0.0017856
567870 | R+2 | Level: R+2 | 0.11994 | 1984 | 0.0017856
567871 | R+2 | Level: R+2 | 0.11994 | 1984 | 0.0017856
567872 | R+2 | Level: R+2 | 0.12084 | 1999 | 0.0017991
567873 | R+2 | Level: R+2 | 0.11814 | 1954 | 0.0017586
567874 | R+2 | Level: R+2 | 0.11814 | 1954 | 0.0017586
567875 | R+2 | Level: R+2 | 0.11814 | 1954 | 0.0017586
567876 | R+2 | Level: R+2 | 0.11814 | 1954 | 0.0017586
567877 | R+2 | Level: R+2 | 0.11814 | 1954 | 0.0017586
567878 | R+2 | Level: R+2 | 0.1047 | 1730 | 0.001557
567879 | R+2 | Level: R+2 | 0.1047 | 1730 | 0.001557
567880 | R+2 | Level: R+2 | 0.1047 | 1730 | 0.001557
567881 | R+2 | Level: R+2 | 0.1047 | 1730 | 0.001557
567882 | R+2 | Level: R+2 | 0.1047 | 1730 | 0.001557
567883 | R+2 | Level: R+2 | 0.1047 | 1730 | 0.001557
567884 | R+2 | Level: R+2 | 0.1047 | 1730 | 0.001557
567885 | R+2 | Level: R+2 | 0.1047 | 1730 | 0.001557
567886 | R+2 | Level: R+2 | 0.1047 | 1730 | 0.001557
567887 | R+2 | Level: R+2 | 0.1047 | 1730 | 0.001557
567888 | R+2 | Level: R+2 | 0.1047 | 1730 | 0.001557
567889 | R+2 | Level: R+2 | 0.1047 | 1730 | 0.001557
567906 | R+1 | Level: R+1 | 0.12084 | 1999 | 0.0017991
567907 | R+1 | Level: R+1 | 0.12084 | 1999 | 0.0017991
567908 | R+1 | Level: R+1 | 0.11994 | 1984 | 0.0017856
567909 | R+1 | Level: R+1 | 0.11994 | 1984 | 0.0017856
567910 | R+1 | Level: R+1 | 0.11994 | 1984 | 0.0017856
567911 | R+1 | Level: R+1 | 0.12084 | 1999 | 0.0017991
567912 | R+1 | Level: R+1 | 0.11994 | 1984 | 0.0017856
567913 | R+1 | Level: R+1 | 0.11994 | 1984 | 0.0017856
567914 | R+1 | Level: R+1 | 0.11994 | 1984 | 0.0017856
567915 | R+1 | Level: R+1 | 0.12084 | 1999 | 0.0017991
567916 | R+1 | Level: R+1 | 0.11814 | 1954 | 0.0017586
567917 | R+1 | Level: R+1 | 0.11814 | 1954 | 0.0017586
567918 | R+1 | Level: R+1 | 0.11814 | 1954 | 0.0017586
567919 | R+1 | Level: R+1 | 0.11814 | 1954 | 0.0017586
567920 | R+1 | Level: R+1 | 0.11814 | 1954 | 0.0017586
567921 | R+1 | Level: R+1 | 0.1047 | 1730 | 0.001557
567922 | R+1 | Level: R+1 | 0.1047 | 1730 | 0.001557
567923 | R+1 | Level: R+1 | 0.1047 | 1730 | 0.001557
567924 | R+1 | Level: R+1 | 0.1047 | 1730 | 0.001557
567925 | R+1 | Level: R+1 | 0.1047 | 1730 | 0.001557
567926 | R+1 | Level: R+1 | 0.1047 | 1730 | 0.001557
567927 | R+1 | Level: R+1 | 0.1047 | 1730 | 0.001557
567928 | R+1 | Level: R+1 | 0.1047 | 1730 | 0.001557
567929 | R+1 | Level: R+1 | 0.1047 | 1730 | 0.001557
567930 | R+1 | Level: R+1 | 0.1047 | 1730 | 0.001557
567931 | R+1 | Level: R+1 | 0.1047 | 1730 | 0.001557
567932 | R+1 | Level: R+1 | 0.1047 | 1730 | 0.001557
569507 | R+1 | Level: R+1 | 0.1365 | 2260 | 0.002034
569508 | R+1 | Level: R+1 | 0.1365 | 2260 | 0.002034
569513 | R+1 | Level: R+1 | 0.060032 | 985.534 | 0.00088698
569514 | R+1 | Level: R+1 | 0.060032 | 985.534 | 0.00088698
569515 | R+1 | Level: R+1 | 0.1338 | 2215 | 0.0019935
569516 | R+1 | Level: R+1 | 0.1338 | 2215 | 0.0019935
569517 | R+1 | Level: R+1 | 0.060032 | 985.534 | 0.00088698
569518 | R+1 | Level: R+1 | 0.060932 | 1000.53 | 0.00090048
569523 | R+1 | Level: R+1 | 0.060932 | 1000.53 | 0.00090048
569524 | R+1 | Level: R+1 | 0.060932 | 1000.53 | 0.00090048
569525 | R+1 | Level: R+1 | 0.1338 | 2215 | 0.0019935
569526 | R+1 | Level: R+1 | 0.1338 | 2215 | 0.0019935
572214 | R+1 | Level: R+1 | 0.060932 | 1000.53 | 0.00090048
572215 | R+1 | Level: R+1 | 0.060932 | 1000.53 | 0.00090048
572216 | R+1 | Level: R+1 | 0.060932 | 1000.53 | 0.00090048
572217 | R+1 | Level: R+1 | 0.060932 | 1000.53 | 0.00090048
572218 | R+1 | Level: R+1 | 0.060932 | 1000.53 | 0.00090048
572224 | R+1 | Level: R+1 | 0.060932 | 1000.53 | 0.00090048
572225 | R+1 | Level: R+1 | 0.060932 | 1000.53 | 0.00090048
572226 | R+1 | Level: R+1 | 0.060932 | 1000.53 | 0.00090048
572227 | R+1 | Level: R+1 | 0.060932 | 1000.53 | 0.00090048
572228 | R+1 | Level: R+1 | 0.060032 | 985.534 | 0.00088698
572229 | R+1 | Level: R+1 | 0.1338 | 2215 | 0.0019935
572230 | R+1 | Level: R+1 | 0.1338 | 2215 | 0.0019935
572231 | R+1 | Level: R+1 | 0.1338 | 2215 | 0.0019935
572232 | R+1 | Level: R+1 | 0.1338 | 2215 | 0.0019935
572233 | R+1 | Level: R+1 | 0.1338 | 2215 | 0.0019935
572234 | R+1 | Level: R+1 | 0.1338 | 2215 | 0.0019935
572235 | R+1 | Level: R+1 | 0.1338 | 2215 | 0.0019935
572236 | R+1 | Level: R+1 | 0.1338 | 2215 | 0.0019935
572237 | R+1 | Level: R+1 | 0.1338 | 2215 | 0.0019935
572238 | R+1 | Level: R+1 | 0.1338 | 2215 | 0.0019935
574552 | R+1 | Level: R+1 | 0.1365 | 2260 | 0.002034
574553 | R+1 | Level: R+1 | 0.1365 | 2260 | 0.002034
574554 | R+1 | Level: R+1 | 0.060032 | 985.534 | 0.00088698
574555 | R+1 | Level: R+1 | 0.060932 | 1000.53 | 0.00090048
574556 | R+1 | Level: R+1 | 0.060932 | 1000.53 | 0.00090048
574557 | R+1 | Level: R+1 | 0.060932 | 1000.53 | 0.00090048
574558 | R+1 | Level: R+1 | 0.060932 | 1000.53 | 0.00090048
574559 | R+1 | Level: R+1 | 0.060932 | 1000.53 | 0.00090048
574560 | R+1 | Level: R+1 | 0.060932 | 1000.53 | 0.00090048
574561 | R+1 | Level: R+1 | 0.060032 | 985.534 | 0.00088698
579482 | R+1 | Level: R+1 | 0.1365 | 2260 | 0.002034
579483 | R+1 | Level: R+1 | 0.1365 | 2260 | 0.002034
579484 | R+1 | Level: R+1 | 0.060032 | 985.534 | 0.00088698
579485 | R+1 | Level: R+1 | 0.060032 | 985.534 | 0.00088698
579486 | R+1 | Level: R+1 | 0.1338 | 2215 | 0.0019935
579487 | R+1 | Level: R+1 | 0.1338 | 2215 | 0.0019935
579488 | R+1 | Level: R+1 | 0.060032 | 985.534 | 0.00088698
579489 | R+1 | Level: R+1 | 0.060932 | 1000.53 | 0.00090048
579493 | R+1 | Level: R+1 | 0.060932 | 1000.53 | 0.00090048
579494 | R+1 | Level: R+1 | 0.060932 | 1000.53 | 0.00090048
579495 | R+1 | Level: R+1 | 0.1338 | 2215 | 0.0019935
579496 | R+1 | Level: R+1 | 0.1338 | 2215 | 0.0019935
579512 | R+1 | Level: R+1 | 0.060932 | 1000.53 | 0.00090048
579513 | R+1 | Level: R+1 | 0.060932 | 1000.53 | 0.00090048
579514 | R+1 | Level: R+1 | 0.060932 | 1000.53 | 0.00090048
579515 | R+1 | Level: R+1 | 0.060932 | 1000.53 | 0.00090048
579516 | R+1 | Level: R+1 | 0.060932 | 1000.53 | 0.00090048
579517 | R+1 | Level: R+1 | 0.060932 | 1000.53 | 0.00090048
579518 | R+1 | Level: R+1 | 0.060932 | 1000.53 | 0.00090048
579519 | R+1 | Level: R+1 | 0.060932 | 1000.53 | 0.00090048
579520 | R+1 | Level: R+1 | 0.060932 | 1000.53 | 0.00090048
579521 | R+1 | Level: R+1 | 0.060032 | 985.534 | 0.00088698
579522 | R+1 | Level: R+1 | 0.1338 | 2215 | 0.0019935
579523 | R+1 | Level: R+1 | 0.1338 | 2215 | 0.0019935
579524 | R+1 | Level: R+1 | 0.1338 | 2215 | 0.0019935
579525 | R+1 | Level: R+1 | 0.1338 | 2215 | 0.0019935
579526 | R+1 | Level: R+1 | 0.1338 | 2215 | 0.0019935
579527 | R+1 | Level: R+1 | 0.1338 | 2215 | 0.0019935
579528 | R+1 | Level: R+1 | 0.1338 | 2215 | 0.0019935
579529 | R+1 | Level: R+1 | 0.1338 | 2215 | 0.0019935
579530 | R+1 | Level: R+1 | 0.1338 | 2215 | 0.0019935
579531 | R+1 | Level: R+1 | 0.1338 | 2215 | 0.0019935
579532 | R+1 | Level: R+1 | 0.1365 | 2260 | 0.002034
579533 | R+1 | Level: R+1 | 0.1365 | 2260 | 0.002034
579534 | R+1 | Level: R+1 | 0.060032 | 985.534 | 0.00088698
579535 | R+1 | Level: R+1 | 0.060932 | 1000.53 | 0.00090048
579536 | R+1 | Level: R+1 | 0.060932 | 1000.53 | 0.00090048
579537 | R+1 | Level: R+1 | 0.060932 | 1000.53 | 0.00090048
579538 | R+1 | Level: R+1 | 0.060932 | 1000.53 | 0.00090048
579539 | R+1 | Level: R+1 | 0.060932 | 1000.53 | 0.00090048
579540 | R+1 | Level: R+1 | 0.060932 | 1000.53 | 0.00090048
579541 | R+1 | Level: R+1 | 0.060032 | 985.534 | 0.00088698

# IfcMember: Rectangular Mullion:50x150mm (167)
In: RDC
Type - PredefinedType: MULLION; Material: Aluminium
Type - Constraints - Angle: 0 deg; Offset: 0 mm
Type - Construction - Corner Mullion: no; Position: Perpendicular to Face; Thickness: 150 mm
Type - Dimensions - Width on side 1: 25 mm; Width on side 2: 25 mm
Type - Identity Data - Keynote: H11; Type Name: 50x150mm
Type - Materials and Finishes - Material: Aluminium
Type - Other - Category: Curtain Wall Mullions; Family Name: Rectangular Mullion
Type - Pset_MemberCommon - IsExternal: no; Reference: 50x150mm
Type - Pset_ProductRequirements - Category: Curtain Wall Mullions
Type - Pset_QuantityTakeOff - Reference: 50x150mm
Constraints - Level: Level: RDC
Other - Family: Rectangular Mullion: 50x150mm; Family and Type: Rectangular Mullion: 50x150mm; Type: Rectangular Mullion: 50x150mm; Type Id: Rectangular Mullion: 50x150mm
Phasing - Phase Created: Existing
Pset_MemberCommon - IsExternal: yes
Name (Rectangular Mullion:50x150mm:...) | Area (m2) | Length (mm) = Span (mm) | Volume (m3) | Host Id
575939 | 0.3105 | 1515 | 0.0113625 | Curtain Wall: Curtain_Wall-Empty
575940 | 0.1365 | 645 | 0.0048375 | Curtain Wall: Curtain_Wall-Empty
575983 | 0.3075 | 1500 | 0.01125 | Curtain Wall: Curtain_Wall-Empty
575984 | 0.1365 | 645 | 0.0048375 | Curtain Wall: Curtain_Wall-Empty
575985 | 0.3105 | 1515 | 0.0113625 | Curtain Wall: Curtain_Wall-Empty
575986 | 0.3075 | 1500 | 0.01125 | Curtain Wall: Curtain_Wall-Empty
576001 | 0.3105 | 1515 | 0.0113625 | Curtain Wall: Curtain_Wall-Empty
576002 | 0.3105 | 1515 | 0.0113625 | Curtain Wall: Curtain_Wall-Empty
576003 | 0.3105 | 1515 | 0.0113625 | Curtain Wall: Curtain_Wall-Empty
576006 | 0.3075 | 1500 | 0.01125 | Curtain Wall: Curtain_Wall-Empty
576007 | 0.3075 | 1500 | 0.01125 | Curtain Wall: Curtain_Wall-Empty
576008 | 0.3075 | 1500 | 0.01125 | Curtain Wall: Curtain_Wall-Empty
576011 | 0.1365 | 645 | 0.0048375 | Curtain Wall: Curtain_Wall-Empty
576012 | 0.1365 | 645 | 0.0048375 | Curtain Wall: Curtain_Wall-Empty
576013 | 0.1365 | 645 | 0.0048375 | Curtain Wall: Curtain_Wall-Empty
576290 | 0.2555 | 1240 | 0.0093 | Curtain Wall: Curtain_Wall-Empty
576291 | 0.4495 | 2210 | 0.016575 | Curtain Wall: Curtain_Wall-Empty
576292 | 0.4495 | 2210 | 0.016575 | Curtain Wall: Curtain_Wall-Empty
576293 | 0.4495 | 2210 | 0.016575 | Curtain Wall: Curtain_Wall-Empty
576294 | 0.4495 | 2210 | 0.016575 | Curtain Wall: Curtain_Wall-Empty
576295 | 0.4495 | 2210 | 0.016575 | Curtain Wall: Curtain_Wall-Empty
576296 | 0.4495 | 2210 | 0.016575 | Curtain Wall: Curtain_Wall-Empty
576297 | 0.2555 | 1240 | 0.0093 | Curtain Wall: Curtain_Wall-Empty
576405 | 0.3105 | 1515 | 0.0113625 | Curtain Wall: Curtain_Wall-Empty
576406 | 0.1365 | 645 | 0.0048375 | Curtain Wall: Curtain_Wall-Empty
576423 | 0.3075 | 1500 | 0.01125 | Curtain Wall: Curtain_Wall-Empty
576424 | 0.1365 | 645 | 0.0048375 | Curtain Wall: Curtain_Wall-Empty
576425 | 0.3105 | 1515 | 0.0113625 | Curtain Wall: Curtain_Wall-Empty
576426 | 0.3075 | 1500 | 0.01125 | Curtain Wall: Curtain_Wall-Empty
576427 | 0.3105 | 1515 | 0.0113625 | Curtain Wall: Curtain_Wall-Empty
576428 | 0.3105 | 1515 | 0.0113625 | Curtain Wall: Curtain_Wall-Empty
576429 | 0.3105 | 1515 | 0.0113625 | Curtain Wall: Curtain_Wall-Empty
576430 | 0.3075 | 1500 | 0.01125 | Curtain Wall: Curtain_Wall-Empty
576431 | 0.3075 | 1500 | 0.01125 | Curtain Wall: Curtain_Wall-Empty
576432 | 0.3075 | 1500 | 0.01125 | Curtain Wall: Curtain_Wall-Empty
576433 | 0.1365 | 645 | 0.0048375 | Curtain Wall: Curtain_Wall-Empty
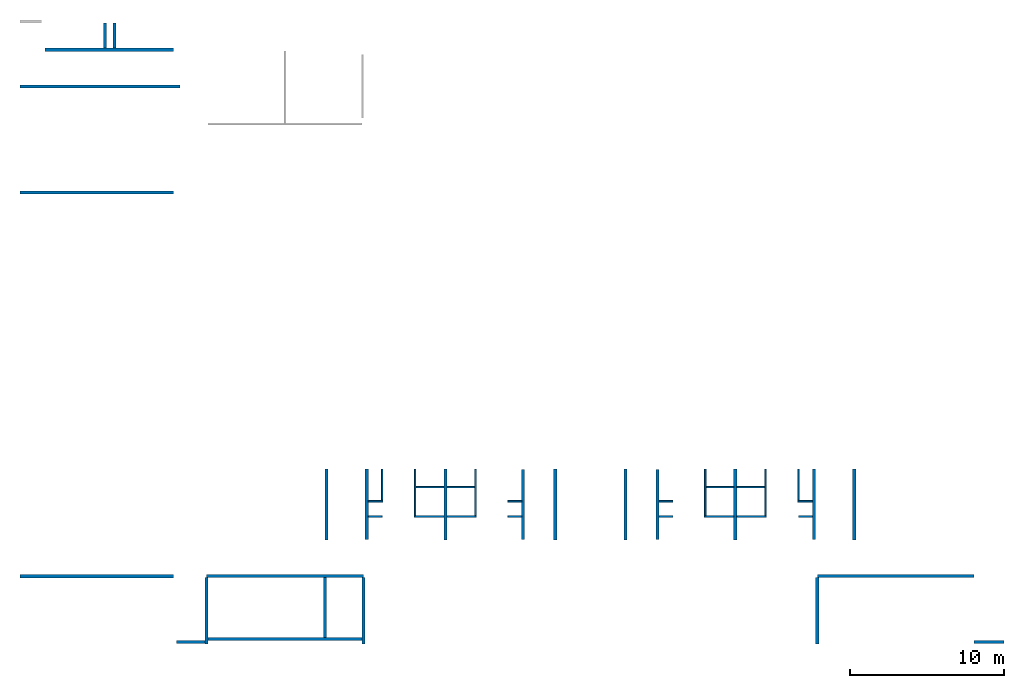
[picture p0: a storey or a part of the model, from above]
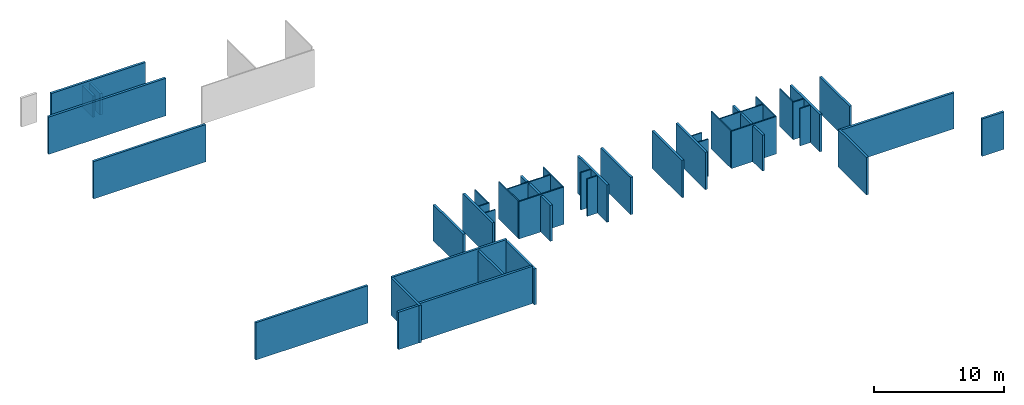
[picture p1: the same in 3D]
Properties of the parts of a building model (IFC2X3), part 2 of 3

# IfcMember: Rectangular Mullion:50x150mm (167)
Name (Rectangular Mullion:50x150mm:...) | Area (m2) | Length (mm) = Span (mm) | Volume (m3) | Host Id
576434 | 0.1365 | 645 | 0.0048375 | Curtain Wall: Curtain_Wall-Empty
576435 | 0.1365 | 645 | 0.0048375 | Curtain Wall: Curtain_Wall-Empty
576436 | 0.2555 | 1240 | 0.0093 | Curtain Wall: Curtain_Wall-Empty
576437 | 0.4495 | 2210 | 0.016575 | Curtain Wall: Curtain_Wall-Empty
576438 | 0.4495 | 2210 | 0.016575 | Curtain Wall: Curtain_Wall-Empty
576439 | 0.4495 | 2210 | 0.016575 | Curtain Wall: Curtain_Wall-Empty
576440 | 0.4495 | 2210 | 0.016575 | Curtain Wall: Curtain_Wall-Empty
576441 | 0.4495 | 2210 | 0.016575 | Curtain Wall: Curtain_Wall-Empty
576442 | 0.4495 | 2210 | 0.016575 | Curtain Wall: Curtain_Wall-Empty
576443 | 0.2555 | 1240 | 0.0093 | Curtain Wall: Curtain_Wall-Empty
576493 | 0.3105 | 1515 | 0.0113625 | Curtain Wall: Curtain_Wall-Empty
576494 | 0.1365 | 645 | 0.0048375 | Curtain Wall: Curtain_Wall-Empty
576511 | 0.3075 | 1500 | 0.01125 | Curtain Wall: Curtain_Wall-Empty
576512 | 0.1365 | 645 | 0.0048375 | Curtain Wall: Curtain_Wall-Empty
576513 | 0.3105 | 1515 | 0.0113625 | Curtain Wall: Curtain_Wall-Empty
576514 | 0.3075 | 1500 | 0.01125 | Curtain Wall: Curtain_Wall-Empty
576515 | 0.3105 | 1515 | 0.0113625 | Curtain Wall: Curtain_Wall-Empty
576516 | 0.3105 | 1515 | 0.0113625 | Curtain Wall: Curtain_Wall-Empty
576517 | 0.3105 | 1515 | 0.0113625 | Curtain Wall: Curtain_Wall-Empty
576518 | 0.3075 | 1500 | 0.01125 | Curtain Wall: Curtain_Wall-Empty
576519 | 0.3075 | 1500 | 0.01125 | Curtain Wall: Curtain_Wall-Empty
576520 | 0.3075 | 1500 | 0.01125 | Curtain Wall: Curtain_Wall-Empty
576521 | 0.1365 | 645 | 0.0048375 | Curtain Wall: Curtain_Wall-Empty
576522 | 0.1365 | 645 | 0.0048375 | Curtain Wall: Curtain_Wall-Empty
576523 | 0.1365 | 645 | 0.0048375 | Curtain Wall: Curtain_Wall-Empty
576524 | 0.1695 | 810 | 0.006075 | Curtain Wall: Curtain_Wall-Empty
576525 | 0.4495 | 2210 | 0.016575 | Curtain Wall: Curtain_Wall-Empty
576526 | 0.4495 | 2210 | 0.016575 | Curtain Wall: Curtain_Wall-Empty
576527 | 0.4495 | 2210 | 0.016575 | Curtain Wall: Curtain_Wall-Empty
576528 | 0.4495 | 2210 | 0.016575 | Curtain Wall: Curtain_Wall-Empty
576529 | 0.4495 | 2210 | 0.016575 | Curtain Wall: Curtain_Wall-Empty
576530 | 0.4495 | 2210 | 0.016575 | Curtain Wall: Curtain_Wall-Empty
576531 | 0.4495 | 2210 | 0.016575 | Curtain Wall: Curtain_Wall-Empty
576680 | 0.4495 | 2210 | 0.016575 | Curtain Wall: Curtain_Wall-Empty
576681 | 0.1695 | 810 | 0.006075 | Curtain Wall: Curtain_Wall-Empty
576682 | 0.3105 | 1515 | 0.0113625 | Curtain Wall: Curtain_Wall-Empty
576683 | 0.3075 | 1500 | 0.01125 | Curtain Wall: Curtain_Wall-Empty
576684 | 0.1365 | 645 | 0.0048375 | Curtain Wall: Curtain_Wall-Empty
576826 | 0.3105 | 1515 | 0.0113625 | Curtain Wall: Curtain_Wall-Empty
576827 | 0.2965 | 1445 | 0.0108375 | Curtain Wall: Curtain_Wall-Empty
576844 | 0.2965 | 1445 | 0.0108375 | Curtain Wall: Curtain_Wall-Empty
576846 | 0.3105 | 1515 | 0.0113625 | Curtain Wall: Curtain_Wall-Empty
576848 | 0.3105 | 1515 | 0.0113625 | Curtain Wall: Curtain_Wall-Empty
576849 | 0.3105 | 1515 | 0.0113625 | Curtain Wall: Curtain_Wall-Empty
576850 | 0.3105 | 1515 | 0.0113625 | Curtain Wall: Curtain_Wall-Empty
576851 | 0.2965 | 1445 | 0.0108375 | Curtain Wall: Curtain_Wall-Empty
576852 | 0.2965 | 1445 | 0.0108375 | Curtain Wall: Curtain_Wall-Empty
576853 | 0.2965 | 1445 | 0.0108375 | Curtain Wall: Curtain_Wall-Empty
576857 | 0.1695 | 810 | 0.006075 | Curtain Wall: Curtain_Wall-Empty
576858 | 0.4495 | 2210 | 0.016575 | Curtain Wall: Curtain_Wall-Empty
576859 | 0.4495 | 2210 | 0.016575 | Curtain Wall: Curtain_Wall-Empty
576860 | 0.4495 | 2210 | 0.016575 | Curtain Wall: Curtain_Wall-Empty
576861 | 0.4495 | 2210 | 0.016575 | Curtain Wall: Curtain_Wall-Empty
576862 | 0.4495 | 2210 | 0.016575 | Curtain Wall: Curtain_Wall-Empty
576863 | 0.4495 | 2210 | 0.016575 | Curtain Wall: Curtain_Wall-Empty
576864 | 0.4495 | 2210 | 0.016575 | Curtain Wall: Curtain_Wall-Empty
576869 | 0.4495 | 2210 | 0.016575 | Curtain Wall: Curtain_Wall-Empty
576870 | 0.1695 | 810 | 0.006075 | Curtain Wall: Curtain_Wall-Empty
576871 | 0.3105 | 1515 | 0.0113625 | Curtain Wall: Curtain_Wall-Empty
576872 | 0.2965 | 1445 | 0.0108375 | Curtain Wall: Curtain_Wall-Empty
577007 | 0.1699 | 812 | 0.00609 | Curtain Wall: Curtain_Wall-Empty
577008 | 0.4495 | 2210 | 0.016575 | Curtain Wall: Curtain_Wall-Empty
577009 | 0.4495 | 2210 | 0.016575 | Curtain Wall: Curtain_Wall-Empty
577010 | 0.4495 | 2210 | 0.016575 | Curtain Wall: Curtain_Wall-Empty
577011 | 0.4495 | 2210 | 0.016575 | Curtain Wall: Curtain_Wall-Empty
577012 | 0.4495 | 2210 | 0.016575 | Curtain Wall: Curtain_Wall-Empty
577013 | 0.4495 | 2210 | 0.016575 | Curtain Wall: Curtain_Wall-Empty
577014 | 0.4495 | 2210 | 0.016575 | Curtain Wall: Curtain_Wall-Empty
577015 | 0.4495 | 2210 | 0.016575 | Curtain Wall: Curtain_Wall-Empty
577016 | 0.1699 | 812 | 0.00609 | Curtain Wall: Curtain_Wall-Empty
577017 | 0.7395 | 3660 | 0.02745 | Curtain Wall: Curtain_Wall-Empty
577018 | 0.7395 | 3660 | 0.02745 | Curtain Wall: Curtain_Wall-Empty
577019 | 0.7395 | 3660 | 0.02745 | Curtain Wall: Curtain_Wall-Empty
577020 | 0.7395 | 3660 | 0.02745 | Curtain Wall: Curtain_Wall-Empty
577021 | 0.7395 | 3660 | 0.02745 | Curtain Wall: Curtain_Wall-Empty
577022 | 0.7395 | 3660 | 0.02745 | Curtain Wall: Curtain_Wall-Empty
577161 | 0.1699 | 812 | 0.00609 | Curtain Wall: Curtain_Wall-Empty
577162 | 0.4495 | 2210 | 0.016575 | Curtain Wall: Curtain_Wall-Empty
577163 | 0.4495 | 2210 | 0.016575 | Curtain Wall: Curtain_Wall-Empty
577164 | 0.4495 | 2210 | 0.016575 | Curtain Wall: Curtain_Wall-Empty
577165 | 0.4495 | 2210 | 0.016575 | Curtain Wall: Curtain_Wall-Empty
577166 | 0.4495 | 2210 | 0.016575 | Curtain Wall: Curtain_Wall-Empty
577167 | 0.4495 | 2210 | 0.016575 | Curtain Wall: Curtain_Wall-Empty
577168 | 0.4495 | 2210 | 0.016575 | Curtain Wall: Curtain_Wall-Empty
577169 | 0.4495 | 2210 | 0.016575 | Curtain Wall: Curtain_Wall-Empty
577170 | 0.1699 | 812 | 0.00609 | Curtain Wall: Curtain_Wall-Empty
577171 | 0.7395 | 3660 | 0.02745 | Curtain Wall: Curtain_Wall-Empty
577172 | 0.7395 | 3660 | 0.02745 | Curtain Wall: Curtain_Wall-Empty
577173 | 0.7395 | 3660 | 0.02745 | Curtain Wall: Curtain_Wall-Empty
577174 | 0.7395 | 3660 | 0.02745 | Curtain Wall: Curtain_Wall-Empty
577175 | 0.7395 | 3660 | 0.02745 | Curtain Wall: Curtain_Wall-Empty
577176 | 0.7395 | 3660 | 0.02745 | Curtain Wall: Curtain_Wall-Empty
577874 | 0.4119 | 2022 | 0.015165 | Curtain Wall: Curtain_Wall-Empty
577875 | 0.4495 | 2210 | 0.016575 | Curtain Wall: Curtain_Wall-Empty
577876 | 0.4495 | 2210 | 0.016575 | Curtain Wall: Curtain_Wall-Empty
577877 | 0.4119 | 2022 | 0.015165 | Curtain Wall: Curtain_Wall-Empty
577878 | 0.7395 | 3660 | 0.02745 | Curtain Wall: Curtain_Wall-Empty
577879 | 0.7395 | 3660 | 0.02745 | Curtain Wall: Curtain_Wall-Empty
577880 | 0.7395 | 3660 | 0.02745 | Curtain Wall: Curtain_Wall-Empty
578341 | 0.1703 | 814 | 0.006105 | Curtain Wall: Curtain_Wall-Empty 2
578342 | 0.4495 | 2210 | 0.016575 | Curtain Wall: Curtain_Wall-Empty 2
578343 | 0.4495 | 2210 | 0.016575 | Curtain Wall: Curtain_Wall-Empty 2
578344 | 0.4495 | 2210 | 0.016575 | Curtain Wall: Curtain_Wall-Empty 2
578345 | 0.4495 | 2210 | 0.016575 | Curtain Wall: Curtain_Wall-Empty 2
578346 | 0.4495 | 2210 | 0.016575 | Curtain Wall: Curtain_Wall-Empty 2
578347 | 0.4495 | 2210 | 0.016575 | Curtain Wall: Curtain_Wall-Empty 2
578348 | 0.4495 | 2210 | 0.016575 | Curtain Wall: Curtain_Wall-Empty 2
578349 | 0.4495 | 2210 | 0.016575 | Curtain Wall: Curtain_Wall-Empty 2
578350 | 0.1703 | 814 | 0.006105 | Curtain Wall: Curtain_Wall-Empty 2
578351 | 0.7395 | 3660 | 0.02745 | Curtain Wall: Curtain_Wall-Empty 2
578352 | 0.7395 | 3660 | 0.02745 | Curtain Wall: Curtain_Wall-Empty 2
578353 | 0.7395 | 3660 | 0.02745 | Curtain Wall: Curtain_Wall-Empty 2
578354 | 0.7395 | 3660 | 0.02745 | Curtain Wall: Curtain_Wall-Empty 2
578355 | 0.7395 | 3660 | 0.02745 | Curtain Wall: Curtain_Wall-Empty 2
578356 | 0.7395 | 3660 | 0.02745 | Curtain Wall: Curtain_Wall-Empty 2
578467 | 0.1703 | 814 | 0.006105 | Curtain Wall: Curtain_Wall-Empty 2
578468 | 0.4495 | 2210 | 0.016575 | Curtain Wall: Curtain_Wall-Empty 2
578469 | 0.4495 | 2210 | 0.016575 | Curtain Wall: Curtain_Wall-Empty 2
578470 | 0.4495 | 2210 | 0.016575 | Curtain Wall: Curtain_Wall-Empty 2
578471 | 0.4495 | 2210 | 0.016575 | Curtain Wall: Curtain_Wall-Empty 2
578472 | 0.4495 | 2210 | 0.016575 | Curtain Wall: Curtain_Wall-Empty 2
578473 | 0.4495 | 2210 | 0.016575 | Curtain Wall: Curtain_Wall-Empty 2
578474 | 0.4495 | 2210 | 0.016575 | Curtain Wall: Curtain_Wall-Empty 2
578475 | 0.4495 | 2210 | 0.016575 | Curtain Wall: Curtain_Wall-Empty 2
578476 | 0.1703 | 814 | 0.006105 | Curtain Wall: Curtain_Wall-Empty 2
578477 | 0.7395 | 3660 | 0.02745 | Curtain Wall: Curtain_Wall-Empty 2
578478 | 0.7395 | 3660 | 0.02745 | Curtain Wall: Curtain_Wall-Empty 2
578479 | 0.7395 | 3660 | 0.02745 | Curtain Wall: Curtain_Wall-Empty 2
578480 | 0.7395 | 3660 | 0.02745 | Curtain Wall: Curtain_Wall-Empty 2
578481 | 0.7395 | 3660 | 0.02745 | Curtain Wall: Curtain_Wall-Empty 2
578482 | 0.7395 | 3660 | 0.02745 | Curtain Wall: Curtain_Wall-Empty 2

# IfcOpeningElement: Opening (16)
Name | In
Entrance windows:Door:533483:1 | RDC
Basic Wall:Wall-Int 100:525360 | RDC | Constraints - Level: Level: RDC; Sill Height: 2 mm; Dimensions - Area: 2.7635 m2; Volume: 0.0334496 m3; Identity Data - Comments: ThisIsExisting; Mark: 20; Other - Category: Windows; Family: Entrance windows: Central; Family and Type: Entrance windows: Central; Head Height: 2342 mm; Host Id: Basic Wall: Wall-Int 100; Type: Entrance windows: Central; Type Id: Entrance windows: Central; Phasing - Phase Created: Existing; Pset_OpeningElementCommon - Reference: Central; sets with these values: 2; Pset_ProductRequirements - Category: Windows
Basic Wall:Wall-Int 100:525360 | RDC | Dimensions - Area: 36.3149 m2; Length: 4520 mm; Identity Data - Comments: ThisIsExisting; Other - Category: Walls; Family: Curtain Wall: Curtain_Wall-Exterior_Glazing; Family and Type: Curtain Wall: Curtain_Wall-Exterior_Glazing; Type: Curtain Wall: Curtain_Wall-Exterior_Glazing; Type Id: Curtain Wall: Curtain_Wall-Exterior_Glazing; Phasing - Phase Created: Existing; Pset_OpeningElementCommon - Reference: Curtain_Wall-Exterior_Glazing; sets with these values: 2; Pset_ProductRequirements - Category: Walls; Constraints - Base is Attached: no; Cross-Section: Vertical; Related to Mass: no; Room Bounding: yes; Top is Attached: no; Base Constraint: Level: R+1; Base Offset: -844.27 mm; Top Constraint: Level: TOP; Top Offset: -380 mm; Unconnected Height: 8034.27 mm; Horizontal Grid - Angle: 0 deg; Justification: Beginning; Number: 7; Offset: 0 mm; Structural - Enable Analytical Model: no; Structural: no; Structural Usage: Non-bearing; Vertical Grid - Angle: 0 deg; Justification: Beginning; Offset: 0 mm; Number: 1
Basic Wall:Wall-Int 100:533480 | RDC | Dimensions - Area: 36.3149 m2; Length: 4520 mm; Identity Data - Comments: ThisIsExisting; Other - Category: Walls; Family: Curtain Wall: Curtain_Wall-Exterior_Glazing; Family and Type: Curtain Wall: Curtain_Wall-Exterior_Glazing; Type: Curtain Wall: Curtain_Wall-Exterior_Glazing; Type Id: Curtain Wall: Curtain_Wall-Exterior_Glazing; Phasing - Phase Created: Existing; Pset_OpeningElementCommon - Reference: Curtain_Wall-Exterior_Glazing; sets with these values: 2; Pset_ProductRequirements - Category: Walls; Constraints - Base is Attached: no; Cross-Section: Vertical; Related to Mass: no; Room Bounding: yes; Top is Attached: no; Base Constraint: Level: R+1; Base Offset: -844.27 mm; Top Constraint: Level: TOP; Top Offset: -380 mm; Unconnected Height: 8034.27 mm; Horizontal Grid - Angle: 0 deg; Justification: Beginning; Number: 7; Offset: 0 mm; Structural - Enable Analytical Model: no; Structural: no; Structural Usage: Non-bearing; Vertical Grid - Angle: 0 deg; Justification: Beginning; Offset: 0 mm; Number: 1
Basic Wall:Wall-Int 100:535950 | R+1 | Dimensions - Area: 35.024 m2; Length: 9950 mm; Identity Data - Comments: ThisIsExisting; Other - Category: Walls; Family: Curtain Wall: Curtain_Wall-Exterior_Glazing; Family and Type: Curtain Wall: Curtain_Wall-Exterior_Glazing; Type: Curtain Wall: Curtain_Wall-Exterior_Glazing; Type Id: Curtain Wall: Curtain_Wall-Exterior_Glazing; Phasing - Phase Created: Existing; Pset_OpeningElementCommon - Reference: Curtain_Wall-Exterior_Glazing; sets with these values: 2; Pset_ProductRequirements - Category: Walls; Constraints - Base is Attached: no; Cross-Section: Vertical; Related to Mass: no; Room Bounding: yes; Top is Attached: no; Base Constraint: Level: R+1; Base Offset: 0 mm; Top Constraint: Level: R+2; Top Offset: -140 mm; Unconnected Height: 3520 mm; Horizontal Grid - Angle: 0 deg; Justification: Beginning; Number: 1; Offset: 0 mm; Structural - Enable Analytical Model: no; Structural: no; Structural Usage: Non-bearing; Vertical Grid - Angle: 0 deg; Justification: Beginning; Offset: 0 mm; Number: 4
Basic Wall:Wall-Int 100:535980 | R+2 | Dimensions - Area: 35.024 m2; Length: 9950 mm; Identity Data - Comments: ThisIsExisting; Other - Category: Walls; Family: Curtain Wall: Curtain_Wall-Exterior_Glazing; Family and Type: Curtain Wall: Curtain_Wall-Exterior_Glazing; Type: Curtain Wall: Curtain_Wall-Exterior_Glazing; Type Id: Curtain Wall: Curtain_Wall-Exterior_Glazing; Phasing - Phase Created: Existing; Pset_OpeningElementCommon - Reference: Curtain_Wall-Exterior_Glazing; sets with these values: 2; Pset_ProductRequirements - Category: Walls; Constraints - Base is Attached: no; Cross-Section: Vertical; Related to Mass: no; Room Bounding: yes; Top is Attached: no; Base Constraint: Level: R+2; Base Offset: 0 mm; Top Constraint: Level: TOITURE; Top Offset: 0 mm; Unconnected Height: 3520 mm; Horizontal Grid - Angle: 0 deg; Justification: Beginning; Number: 1; Offset: 0 mm; Structural - Enable Analytical Model: no; Structural: no; Structural Usage: Non-bearing; Vertical Grid - Angle: 0 deg; Justification: Beginning; Offset: 0 mm; Number: 4
Entrance windows:Door:533484:1 | RDC
Entrance windows:Door:533485:1 | RDC
Entrance windows:Entrance windows:533481:1 | RDC
Entrance windows:Short:533482:1 | RDC
Entrance windows:Central:534478:1 | RDC
Entrance windows:Door:531310:1 | RDC
Entrance windows:Door:531570:1 | RDC
Entrance windows:Door:531658:1 | RDC
Entrance windows:Entrance windows:527844:1 | RDC
Entrance windows:Short:530175:1 | RDC

# IfcPlate: System Panel:Glazed (143)
Type - PredefinedType: CURTAIN_PANEL; Material: Glass
Type - Analytical Properties - Define Thermal Properties by: Schematic Type; Analytic Construction: 1/8 in Pilkington single glazing; Heat Transfer Coefficient (U): 6.7069; Solar Heat Gain Coefficient: 0.86; Thermal Resistance (R): 0.1491; Visual Light Transmittance: 0.9
Type - Constraints - Offset: 37 mm
Type - Dimensions - Thickness: 25 mm
Type - Identity Data - Keynote: H11; Type Name: Glazed
Type - Materials and Finishes - Material: Glass
Type - Other - Category: Curtain Panels; Family Name: System Panel
Type - Pset_PlateCommon - IsExternal: no; Reference: Glazed; ThermalTransmittance: 6.7069 kg/K/s3
Type - Pset_ProductRequirements - Category: Curtain Panels
Type - Pset_QuantityTakeOff - Reference: Glazed
Other - Family: System Panel: Glazed; Family and Type: System Panel: Glazed; Type: System Panel: Glazed; Type Id: System Panel: Glazed
Phasing - Phase Created: Existing
Pset_PlateCommon - IsExternal: yes
Name (System Panel:Glazed:...) | In | Level | Area (m2) | Height (mm) | Volume (m3) | Width (mm) | Host Id
567058 | R+2 | Level: R+2 | 3.51824 | 1760 | 0.087956 | 1999 | Curtain Wall: Curtain_Wall-Exterior_Glazing
567063 | R+2 | Level: R+2 | 3.49184 | 1760 | 0.087296 | 1984 | Curtain Wall: Curtain_Wall-Exterior_Glazing
567258 | R+2 | Level: R+2 | 3.49184 | 1760 | 0.087296 | 1984 | Curtain Wall: Curtain_Wall-Exterior_Glazing
567264 | R+2 | Level: R+2 | 3.49184 | 1760 | 0.087296 | 1984 | Curtain Wall: Curtain_Wall-Exterior_Glazing
567270 | R+2 | Level: R+2 | 3.51824 | 1760 | 0.087956 | 1999 | Curtain Wall: Curtain_Wall-Exterior_Glazing
567162 | R+2 | Level: R+2 | 3.51824 | 1760 | 0.087956 | 1999 | Curtain Wall: Curtain_Wall-Exterior_Glazing
567163 | R+2 | Level: R+2 | 3.49184 | 1760 | 0.087296 | 1984 | Curtain Wall: Curtain_Wall-Exterior_Glazing
567259 | R+2 | Level: R+2 | 3.49184 | 1760 | 0.087296 | 1984 | Curtain Wall: Curtain_Wall-Exterior_Glazing
567265 | R+2 | Level: R+2 | 3.49184 | 1760 | 0.087296 | 1984 | Curtain Wall: Curtain_Wall-Exterior_Glazing
567271 | R+2 | Level: R+2 | 3.51824 | 1760 | 0.087956 | 1999 | Curtain Wall: Curtain_Wall-Exterior_Glazing
567786 | R+1 | Level: R+1 | 3.51824 | 1760 | 0.087956 | 1999 | Curtain Wall: Curtain_Wall-Exterior_Glazing
567788 | R+1 | Level: R+1 | 3.49184 | 1760 | 0.087296 | 1984 | Curtain Wall: Curtain_Wall-Exterior_Glazing
567793 | R+1 | Level: R+1 | 3.49184 | 1760 | 0.087296 | 1984 | Curtain Wall: Curtain_Wall-Exterior_Glazing
567796 | R+1 | Level: R+1 | 3.49184 | 1760 | 0.087296 | 1984 | Curtain Wall: Curtain_Wall-Exterior_Glazing
567799 | R+1 | Level: R+1 | 3.51824 | 1760 | 0.087956 | 1999 | Curtain Wall: Curtain_Wall-Exterior_Glazing
567790 | R+1 | Level: R+1 | 3.51824 | 1760 | 0.087956 | 1999 | Curtain Wall: Curtain_Wall-Exterior_Glazing
567791 | R+1 | Level: R+1 | 3.49184 | 1760 | 0.087296 | 1984 | Curtain Wall: Curtain_Wall-Exterior_Glazing
567794 | R+1 | Level: R+1 | 3.49184 | 1760 | 0.087296 | 1984 | Curtain Wall: Curtain_Wall-Exterior_Glazing
567797 | R+1 | Level: R+1 | 3.49184 | 1760 | 0.087296 | 1984 | Curtain Wall: Curtain_Wall-Exterior_Glazing
567800 | R+1 | Level: R+1 | 3.51824 | 1760 | 0.087956 | 1999 | Curtain Wall: Curtain_Wall-Exterior_Glazing
567848 | R+2 | Level: R+2 | 3.51824 | 1760 | 0.087956 | 1999 | Curtain Wall: Curtain_Wall-Exterior_Glazing
567850 | R+2 | Level: R+2 | 3.49184 | 1760 | 0.087296 | 1984 | Curtain Wall: Curtain_Wall-Exterior_Glazing
567855 | R+2 | Level: R+2 | 3.49184 | 1760 | 0.087296 | 1984 | Curtain Wall: Curtain_Wall-Exterior_Glazing
567858 | R+2 | Level: R+2 | 3.49184 | 1760 | 0.087296 | 1984 | Curtain Wall: Curtain_Wall-Exterior_Glazing
567861 | R+2 | Level: R+2 | 3.51824 | 1760 | 0.087956 | 1999 | Curtain Wall: Curtain_Wall-Exterior_Glazing
567852 | R+2 | Level: R+2 | 3.51824 | 1760 | 0.087956 | 1999 | Curtain Wall: Curtain_Wall-Exterior_Glazing
567853 | R+2 | Level: R+2 | 3.49184 | 1760 | 0.087296 | 1984 | Curtain Wall: Curtain_Wall-Exterior_Glazing
567856 | R+2 | Level: R+2 | 3.49184 | 1760 | 0.087296 | 1984 | Curtain Wall: Curtain_Wall-Exterior_Glazing
567859 | R+2 | Level: R+2 | 3.49184 | 1760 | 0.087296 | 1984 | Curtain Wall: Curtain_Wall-Exterior_Glazing
567862 | R+2 | Level: R+2 | 3.51824 | 1760 | 0.087956 | 1999 | Curtain Wall: Curtain_Wall-Exterior_Glazing
567891 | R+1 | Level: R+1 | 3.51824 | 1760 | 0.087956 | 1999 | Curtain Wall: Curtain_Wall-Exterior_Glazing
567893 | R+1 | Level: R+1 | 3.49184 | 1760 | 0.087296 | 1984 | Curtain Wall: Curtain_Wall-Exterior_Glazing
567898 | R+1 | Level: R+1 | 3.49184 | 1760 | 0.087296 | 1984 | Curtain Wall: Curtain_Wall-Exterior_Glazing
567901 | R+1 | Level: R+1 | 3.49184 | 1760 | 0.087296 | 1984 | Curtain Wall: Curtain_Wall-Exterior_Glazing
567904 | R+1 | Level: R+1 | 3.51824 | 1760 | 0.087956 | 1999 | Curtain Wall: Curtain_Wall-Exterior_Glazing
567895 | R+1 | Level: R+1 | 3.51824 | 1760 | 0.087956 | 1999 | Curtain Wall: Curtain_Wall-Exterior_Glazing
567896 | R+1 | Level: R+1 | 3.49184 | 1760 | 0.087296 | 1984 | Curtain Wall: Curtain_Wall-Exterior_Glazing
567899 | R+1 | Level: R+1 | 3.49184 | 1760 | 0.087296 | 1984 | Curtain Wall: Curtain_Wall-Exterior_Glazing
567902 | R+1 | Level: R+1 | 3.49184 | 1760 | 0.087296 | 1984 | Curtain Wall: Curtain_Wall-Exterior_Glazing
567905 | R+1 | Level: R+1 | 3.51824 | 1760 | 0.087956 | 1999 | Curtain Wall: Curtain_Wall-Exterior_Glazing
569501 | R+1 | Level: R+1 | 2.29511 | 1015.53 | 0.0573777 | 2260 | Curtain Wall: Curtain_Wall-Exterior_Glazing
569503 | R+1 | Level: R+1 | 2.29511 | 1015.53 | 0.0573777 | 2260 | Curtain Wall: Curtain_Wall-Exterior_Glazing
569505 | R+1 | Level: R+1 | 2.26121 | 1000.53 | 0.0565302 | 2260 | Curtain Wall: Curtain_Wall-Exterior_Glazing
569506 | R+1 | Level: R+1 | 2.26121 | 1000.53 | 0.0565302 | 2260 | Curtain Wall: Curtain_Wall-Exterior_Glazing
569520 | R+1 | Level: R+1 | 2.26121 | 1000.53 | 0.0565302 | 2260 | Curtain Wall: Curtain_Wall-Exterior_Glazing
569521 | R+1 | Level: R+1 | 2.26121 | 1000.53 | 0.0565302 | 2260 | Curtain Wall: Curtain_Wall-Exterior_Glazing
572194 | R+1 | Level: R+1 | 2.26121 | 1000.53 | 0.0565302 | 2260 | Curtain Wall: Curtain_Wall-Exterior_Glazing
572195 | R+1 | Level: R+1 | 2.26121 | 1000.53 | 0.0565302 | 2260 | Curtain Wall: Curtain_Wall-Exterior_Glazing
572197 | R+1 | Level: R+1 | 2.26121 | 1000.53 | 0.0565302 | 2260 | Curtain Wall: Curtain_Wall-Exterior_Glazing
572198 | R+1 | Level: R+1 | 2.26121 | 1000.53 | 0.0565302 | 2260 | Curtain Wall: Curtain_Wall-Exterior_Glazing
572200 | R+1 | Level: R+1 | 2.26121 | 1000.53 | 0.0565302 | 2260 | Curtain Wall: Curtain_Wall-Exterior_Glazing
572201 | R+1 | Level: R+1 | 2.26121 | 1000.53 | 0.0565302 | 2260 | Curtain Wall: Curtain_Wall-Exterior_Glazing
572203 | R+1 | Level: R+1 | 2.26121 | 1000.53 | 0.0565302 | 2260 | Curtain Wall: Curtain_Wall-Exterior_Glazing
572204 | R+1 | Level: R+1 | 2.26121 | 1000.53 | 0.0565302 | 2260 | Curtain Wall: Curtain_Wall-Exterior_Glazing
572206 | R+1 | Level: R+1 | 2.29511 | 1015.53 | 0.0573777 | 2260 | Curtain Wall: Curtain_Wall-Exterior_Glazing
572207 | R+1 | Level: R+1 | 2.29511 | 1015.53 | 0.0573777 | 2260 | Curtain Wall: Curtain_Wall-Exterior_Glazing
575832 | RDC | Level: RDC | 3.23765 | 1465 | 0.0809413 | 2210 | Curtain Wall: Curtain_Wall-Empty
575946 | RDC | Level: RDC | 3.23765 | 1465 | 0.0809413 | 2210 | Curtain Wall: Curtain_Wall-Empty
575948 | RDC | Level: RDC | 3.23765 | 1465 | 0.0809413 | 2210 | Curtain Wall: Curtain_Wall-Empty
575950 | RDC | Level: RDC | 1.8166 | 1465 | 0.045415 | 1240 | Curtain Wall: Curtain_Wall-Empty
575952 | RDC | Level: RDC | 3.315 | 1500 | 0.082875 | 2210 | Curtain Wall: Curtain_Wall-Empty
575955 | RDC | Level: RDC | 3.315 | 1500 | 0.082875 | 2210 | Curtain Wall: Curtain_Wall-Empty
575956 | RDC | Level: RDC | 3.315 | 1500 | 0.082875 | 2210 | Curtain Wall: Curtain_Wall-Empty
575957 | RDC | Level: RDC | 1.86 | 1500 | 0.0465 | 1240 | Curtain Wall: Curtain_Wall-Empty
575959 | RDC | Level: RDC | 1.31495 | 595 | 0.0328738 | 2210 | Curtain Wall: Curtain_Wall-Empty
575962 | RDC | Level: RDC | 1.31495 | 595 | 0.0328738 | 2210 | Curtain Wall: Curtain_Wall-Empty
575963 | RDC | Level: RDC | 1.31495 | 595 | 0.0328738 | 2210 | Curtain Wall: Curtain_Wall-Empty
575964 | RDC | Level: RDC | 0.7378 | 595 | 0.018445 | 1240 | Curtain Wall: Curtain_Wall-Empty
576404 | RDC | Level: RDC | 3.23765 | 1465 | 0.0809413 | 2210 | Curtain Wall: Curtain_Wall-Empty
576408 | RDC | Level: RDC | 3.23765 | 1465 | 0.0809413 | 2210 | Curtain Wall: Curtain_Wall-Empty
576410 | RDC | Level: RDC | 3.23765 | 1465 | 0.0809413 | 2210 | Curtain Wall: Curtain_Wall-Empty
576412 | RDC | Level: RDC | 1.8166 | 1465 | 0.045415 | 1240 | Curtain Wall: Curtain_Wall-Empty
576414 | RDC | Level: RDC | 3.315 | 1500 | 0.082875 | 2210 | Curtain Wall: Curtain_Wall-Empty
576415 | RDC | Level: RDC | 3.315 | 1500 | 0.082875 | 2210 | Curtain Wall: Curtain_Wall-Empty
576416 | RDC | Level: RDC | 3.315 | 1500 | 0.082875 | 2210 | Curtain Wall: Curtain_Wall-Empty
576417 | RDC | Level: RDC | 1.86 | 1500 | 0.0465 | 1240 | Curtain Wall: Curtain_Wall-Empty
576419 | RDC | Level: RDC | 1.31495 | 595 | 0.0328738 | 2210 | Curtain Wall: Curtain_Wall-Empty
576420 | RDC | Level: RDC | 1.31495 | 595 | 0.0328738 | 2210 | Curtain Wall: Curtain_Wall-Empty
576421 | RDC | Level: RDC | 1.31495 | 595 | 0.0328738 | 2210 | Curtain Wall: Curtain_Wall-Empty
576422 | RDC | Level: RDC | 0.7378 | 595 | 0.018445 | 1240 | Curtain Wall: Curtain_Wall-Empty
576492 | RDC | Level: RDC | 3.23765 | 1465 | 0.0809413 | 2210 | Curtain Wall: Curtain_Wall-Empty
576496 | RDC | Level: RDC | 3.23765 | 1465 | 0.0809413 | 2210 | Curtain Wall: Curtain_Wall-Empty
576498 | RDC | Level: RDC | 3.23765 | 1465 | 0.0809413 | 2210 | Curtain Wall: Curtain_Wall-Empty
576500 | RDC | Level: RDC | 3.23765 | 1465 | 0.0809413 | 2210 | Curtain Wall: Curtain_Wall-Empty
576668 | RDC | Level: RDC | 1.18665 | 1465 | 0.0296662 | 810 | Curtain Wall: Curtain_Wall-Empty
576502 | RDC | Level: RDC | 3.315 | 1500 | 0.082875 | 2210 | Curtain Wall: Curtain_Wall-Empty
576503 | RDC | Level: RDC | 3.315 | 1500 | 0.082875 | 2210 | Curtain Wall: Curtain_Wall-Empty
576504 | RDC | Level: RDC | 3.315 | 1500 | 0.082875 | 2210 | Curtain Wall: Curtain_Wall-Empty
576505 | RDC | Level: RDC | 3.315 | 1500 | 0.082875 | 2210 | Curtain Wall: Curtain_Wall-Empty
576669 | RDC | Level: RDC | 1.215 | 1500 | 0.030375 | 810 | Curtain Wall: Curtain_Wall-Empty
576507 | RDC | Level: RDC | 1.31495 | 595 | 0.0328738 | 2210 | Curtain Wall: Curtain_Wall-Empty
576508 | RDC | Level: RDC | 1.31495 | 595 | 0.0328738 | 2210 | Curtain Wall: Curtain_Wall-Empty
576509 | RDC | Level: RDC | 1.31495 | 595 | 0.0328738 | 2210 | Curtain Wall: Curtain_Wall-Empty
576510 | RDC | Level: RDC | 1.31495 | 595 | 0.0328738 | 2210 | Curtain Wall: Curtain_Wall-Empty
576670 | RDC | Level: RDC | 0.48195 | 595 | 0.0120487 | 810 | Curtain Wall: Curtain_Wall-Empty
576825 | RDC | Level: RDC | 3.23765 | 1465 | 0.0809413 | 2210 | Curtain Wall: Curtain_Wall-Empty
576829 | RDC | Level: RDC | 3.23765 | 1465 | 0.0809413 | 2210 | Curtain Wall: Curtain_Wall-Empty
576831 | RDC | Level: RDC | 3.23765 | 1465 | 0.0809413 | 2210 | Curtain Wall: Curtain_Wall-Empty
576833 | RDC | Level: RDC | 3.23765 | 1465 | 0.0809413 | 2210 | Curtain Wall: Curtain_Wall-Empty
576866 | RDC | Level: RDC | 1.18665 | 1465 | 0.0296662 | 810 | Curtain Wall: Curtain_Wall-Empty
576835 | RDC | Level: RDC | 3.08295 | 1395 | 0.0770738 | 2210 | Curtain Wall: Curtain_Wall-Empty
576836 | RDC | Level: RDC | 3.08295 | 1395 | 0.0770738 | 2210 | Curtain Wall: Curtain_Wall-Empty
576837 | RDC | Level: RDC | 3.08295 | 1395 | 0.0770738 | 2210 | Curtain Wall: Curtain_Wall-Empty
576838 | RDC | Level: RDC | 3.08295 | 1395 | 0.0770738 | 2210 | Curtain Wall: Curtain_Wall-Empty
576867 | RDC | Level: RDC | 1.12995 | 1395 | 0.0282487 | 810 | Curtain Wall: Curtain_Wall-Empty
576993 | RDC | Level: RDC | 7.8676 | 3560 | 0.19669 | 2210 | Curtain Wall: Curtain_Wall-Empty
576998 | RDC | Level: RDC | 7.8676 | 3560 | 0.19669 | 2210 | Curtain Wall: Curtain_Wall-Empty
577000 | RDC | Level: RDC | 7.8676 | 3560 | 0.19669 | 2210 | Curtain Wall: Curtain_Wall-Empty
577002 | RDC | Level: RDC | 7.8676 | 3560 | 0.19669 | 2210 | Curtain Wall: Curtain_Wall-Empty
577004 | RDC | Level: RDC | 2.89072 | 3560 | 0.072268 | 812 | Curtain Wall: Curtain_Wall-Empty
577152 | RDC | Level: RDC | 7.8676 | 3560 | 0.19669 | 2210 | Curtain Wall: Curtain_Wall-Empty
577154 | RDC | Level: RDC | 7.8676 | 3560 | 0.19669 | 2210 | Curtain Wall: Curtain_Wall-Empty
577156 | RDC | Level: RDC | 7.8676 | 3560 | 0.19669 | 2210 | Curtain Wall: Curtain_Wall-Empty
577158 | RDC | Level: RDC | 7.8676 | 3560 | 0.19669 | 2210 | Curtain Wall: Curtain_Wall-Empty
577160 | RDC | Level: RDC | 2.89072 | 3560 | 0.072268 | 812 | Curtain Wall: Curtain_Wall-Empty
577866 | RDC | Level: RDC | 7.8676 | 3560 | 0.19669 | 2210 | Curtain Wall: Curtain_Wall-Empty
577871 | RDC | Level: RDC | 7.19832 | 3560 | 0.179958 | 2022 | Curtain Wall: Curtain_Wall-Empty
578328 | RDC | Level: RDC | 7.8676 | 3560 | 0.19669 | 2210 | Curtain Wall: Curtain_Wall-Empty 2
578332 | RDC | Level: RDC | 7.8676 | 3560 | 0.19669 | 2210 | Curtain Wall: Curtain_Wall-Empty 2
578334 | RDC | Level: RDC | 7.8676 | 3560 | 0.19669 | 2210 | Curtain Wall: Curtain_Wall-Empty 2
578336 | RDC | Level: RDC | 7.8676 | 3560 | 0.19669 | 2210 | Curtain Wall: Curtain_Wall-Empty 2
578338 | RDC | Level: RDC | 2.89784 | 3560 | 0.072446 | 814 | Curtain Wall: Curtain_Wall-Empty 2
578458 | RDC | Level: RDC | 7.8676 | 3560 | 0.19669 | 2210 | Curtain Wall: Curtain_Wall-Empty 2
578460 | RDC | Level: RDC | 7.8676 | 3560 | 0.19669 | 2210 | Curtain Wall: Curtain_Wall-Empty 2
578462 | RDC | Level: RDC | 7.8676 | 3560 | 0.19669 | 2210 | Curtain Wall: Curtain_Wall-Empty 2
578464 | RDC | Level: RDC | 7.8676 | 3560 | 0.19669 | 2210 | Curtain Wall: Curtain_Wall-Empty 2
578466 | RDC | Level: RDC | 2.89784 | 3560 | 0.072446 | 814 | Curtain Wall: Curtain_Wall-Empty 2
579476 | R+1 | Level: R+1 | 2.29511 | 1015.53 | 0.0573777 | 2260 | Curtain Wall: Curtain_Wall-Exterior_Glazing
579478 | R+1 | Level: R+1 | 2.29511 | 1015.53 | 0.0573777 | 2260 | Curtain Wall: Curtain_Wall-Exterior_Glazing
579480 | R+1 | Level: R+1 | 2.26121 | 1000.53 | 0.0565302 | 2260 | Curtain Wall: Curtain_Wall-Exterior_Glazing
579481 | R+1 | Level: R+1 | 2.26121 | 1000.53 | 0.0565302 | 2260 | Curtain Wall: Curtain_Wall-Exterior_Glazing
579491 | R+1 | Level: R+1 | 2.26121 | 1000.53 | 0.0565302 | 2260 | Curtain Wall: Curtain_Wall-Exterior_Glazing
579492 | R+1 | Level: R+1 | 2.26121 | 1000.53 | 0.0565302 | 2260 | Curtain Wall: Curtain_Wall-Exterior_Glazing
579498 | R+1 | Level: R+1 | 2.26121 | 1000.53 | 0.0565302 | 2260 | Curtain Wall: Curtain_Wall-Exterior_Glazing
579499 | R+1 | Level: R+1 | 2.26121 | 1000.53 | 0.0565302 | 2260 | Curtain Wall: Curtain_Wall-Exterior_Glazing
579501 | R+1 | Level: R+1 | 2.26121 | 1000.53 | 0.0565302 | 2260 | Curtain Wall: Curtain_Wall-Exterior_Glazing
579502 | R+1 | Level: R+1 | 2.26121 | 1000.53 | 0.0565302 | 2260 | Curtain Wall: Curtain_Wall-Exterior_Glazing
579504 | R+1 | Level: R+1 | 2.26121 | 1000.53 | 0.0565302 | 2260 | Curtain Wall: Curtain_Wall-Exterior_Glazing
579505 | R+1 | Level: R+1 | 2.26121 | 1000.53 | 0.0565302 | 2260 | Curtain Wall: Curtain_Wall-Exterior_Glazing
579507 | R+1 | Level: R+1 | 2.26121 | 1000.53 | 0.0565302 | 2260 | Curtain Wall: Curtain_Wall-Exterior_Glazing
579508 | R+1 | Level: R+1 | 2.26121 | 1000.53 | 0.0565302 | 2260 | Curtain Wall: Curtain_Wall-Exterior_Glazing
579510 | R+1 | Level: R+1 | 2.29511 | 1015.53 | 0.0573777 | 2260 | Curtain Wall: Curtain_Wall-Exterior_Glazing
579511 | R+1 | Level: R+1 | 2.29511 | 1015.53 | 0.0573777 | 2260 | Curtain Wall: Curtain_Wall-Exterior_Glazing

# IfcWallStandardCase: Basic Wall:Mur S/SOL 20 (3)
Type - PredefinedType: STANDARD; Material: Concrete - Cast-in-Place Concrete 200 mm
Type - Analytical Properties - Roughness: 3; Absorptance: 0.7
Type - Construction - Wrapping at Inserts: Both; Function: Exterior; Width: 200 mm
Type - Graphics - Coarse Scale Fill Pattern: <Solid fill>; Coarse Scale Fill Color: 12632256
Type - Identity Data - Keynote: F10; Type Name: Mur S/SOL 20
Type - Materials and Finishes - Structural Material: Concrete - Cast-in-Place Concrete
Type - Other - Category: Walls; Family Name: Basic Wall
Type - Pset_ElementShading - Roughness: 914.4 mm
Type - Pset_ProductRequirements - Category: Walls
Type - Pset_QuantityTakeOff - Reference: Mur S/SOL 20
Type - Pset_ReinforcementBarPitchOfWall - Reference: Mur S/SOL 20
Type - Pset_WallCommon - IsExternal: no; Reference: Mur S/SOL 20
Constraints - Base Extension Distance: 0 mm; Base is Attached: no; Base Offset: 0 mm; Cross-Section: Vertical; Related to Mass: no; Room Bounding: yes; Top Extension Distance: 0 mm; Top is Attached: no; Top Offset: 0 mm; Location Line: Finish Face: Exterior
Other - Family: Basic Wall: Mur S/SOL 20; Family and Type: Basic Wall: Mur S/SOL 20; Type: Basic Wall: Mur S/SOL 20; Type Id: Basic Wall: Mur S/SOL 20
Phasing - Phase Created: Existing
Pset_QuantityTakeOff - sets with these values: 2
Pset_WallCommon - ExtendToStructure: no; IsExternal: yes
Name (Basic Wall:Mur S/SOL 20:...) | In | Base Constraint | Unconnected Height (mm) | Area (m2) | Length (mm) | Volume (m3) | ElementID | Enable Analytical Model = Structural = LoadBearing | Rebar Cover - Exterior Face = Rebar Cover - Interior Face = Rebar Cover - Other Faces | Structural Usage
492767 | R-1 | Level: R-1 | 2000 | 3.3 | 1840 | 0.66 | 492767 | yes | Rebar Cover Settings: Rebar Cover 1 | Bearing
492980 | R-1 | Level: R-1 | 2000 | 3.3 | 1840 | 0.66 | 492980 | yes | Rebar Cover Settings: Rebar Cover 1 | Bearing
548321 | R+2 | Level: R+2 | 3520 | 4.94208 | 1404 | 0.988416 |  | no |  | Non-bearing | Constraints - Top Constraint: Level: TOITURE; Identity Data - Comments: ThisIsExisting

# IfcWallStandardCase: Basic Wall:Mur S/SOL 21 (2)
In: R-1
Type - PredefinedType: STANDARD; Material: Concrete - Cast-in-Place Concrete 210 mm
Type - Analytical Properties - Roughness: 3; Absorptance: 0.7
Type - Construction - Wrapping at Inserts: Both; Function: Exterior; Width: 210 mm
Type - Graphics - Coarse Scale Fill Pattern: <Solid fill>; Coarse Scale Fill Color: 12632256
Type - Identity Data - Keynote: F10; Type Name: Mur S/SOL 21
Type - Materials and Finishes - Structural Material: Concrete - Cast-in-Place Concrete
Type - Other - Category: Walls; Family Name: Basic Wall
Type - Pset_ElementShading - Roughness: 914.4 mm
Type - Pset_ProductRequirements - Category: Walls
Type - Pset_QuantityTakeOff - Reference: Mur S/SOL 21
Type - Pset_ReinforcementBarPitchOfWall - Reference: Mur S/SOL 21
Type - Pset_WallCommon - IsExternal: no; Reference: Mur S/SOL 21
Constraints - Base Constraint: Level: R-1; Base Extension Distance: 0 mm; Base is Attached: no; Base Offset: 0 mm; Cross-Section: Vertical; Related to Mass: no; Room Bounding: yes; Top Constraint: Level: RDC; Top Extension Distance: 0 mm; Top is Attached: no
Other - Family: Basic Wall: Mur S/SOL 21; Family and Type: Basic Wall: Mur S/SOL 21; Type: Basic Wall: Mur S/SOL 21; Type Id: Basic Wall: Mur S/SOL 21
Phasing - Phase Created: Existing
Structural - Enable Analytical Model: yes; Rebar Cover - Exterior Face: Rebar Cover Settings: Rebar Cover 1; Rebar Cover - Interior Face: Rebar Cover Settings: Rebar Cover 1; Rebar Cover - Other Faces: Rebar Cover Settings: Rebar Cover 1; Structural: yes; Structural Usage: Bearing
Pset_QuantityTakeOff - sets with these values: 2
Pset_WallCommon - ExtendToStructure: no; IsExternal: yes; LoadBearing: yes
Name (Basic Wall:Mur S/SOL 21:...) | Location Line | Top Offset (mm) | Unconnected Height (mm) | Area (m2) | Length (mm) | Volume (m3) | ElementID
494140 | Finish Face: Exterior | -800 | 2700 | 3.7854 | 1402 | 0.794934 | 494140
495766 | Core Centerline | 0 | 3500 | 36.33 | 10380 | 7.6293 | 495766

# IfcWallStandardCase: Basic Wall:Mur200PentureBlanche 2 (79)
Type - PredefinedType: STANDARD; Material: Paint - White Lining 15 mm, Concrete - Precast Concrete - 35 MPa 200 mm, Paint - White Lining 15 mm
Type - Analytical Properties - Roughness: 3; Absorptance: 0.7
Type - Construction - Function: Interior; Wrapping at Inserts: Both; Width: 230 mm
Type - Graphics - Coarse Scale Fill Pattern: <Solid fill>; Coarse Scale Fill Color: 12632256
Type - Identity Data - Keynote: F10; Type Name: Mur200PentureBlanche 2
Type - Materials and Finishes - Structural Material: Concrete - Precast Concrete - 35 MPa
Type - Other - Category: Walls; Family Name: Basic Wall
Type - Pset_ElementShading - Roughness: 914.4 mm
Type - Pset_ProductRequirements - Category: Walls
Type - Pset_QuantityTakeOff - Reference: Mur200PentureBlanche 2
Type - Pset_ReinforcementBarPitchOfWall - Reference: Mur200PentureBlanche 2
Type - Pset_WallCommon - IsExternal: no; Reference: Mur200PentureBlanche 2
Constraints - Base Extension Distance: 0 mm; Base is Attached: no; Base Offset: 0 mm; Cross-Section: Vertical; Related to Mass: no; Room Bounding: yes; Top Extension Distance: 0 mm; Unconnected Height: 3660 mm
Other - Family: Basic Wall: Mur200PentureBlanche 2; Family and Type: Basic Wall: Mur200PentureBlanche 2; Type: Basic Wall: Mur200PentureBlanche 2; Type Id: Basic Wall: Mur200PentureBlanche 2
Phasing - Phase Created: Existing
Structural - Enable Analytical Model: no; Structural: no; Structural Usage: Non-bearing
Pset_QuantityTakeOff - sets with these values: 2
Pset_WallCommon - LoadBearing: no
Name (Basic Wall:Mur200PentureBlanche 2:...) | In | Location Line | Top Offset (mm) | Top is Attached = ExtendToStructure | Base Constraint | Top Constraint | Area (m2) | Length (mm) | Volume (m3) | ElementID | Comments
452318 | RDC | Core Face: Exterior | 0 | yes | Level: RDC | Level: R+1 | 8.03075 | 2160 | 1.84707 | 452318
452415 | RDC | Core Face: Exterior | 0 | yes | Level: RDC | Level: R+1 | 7.9072 | 2125 | 1.81866 | 452415
452492 | RDC | Core Face: Exterior | 0 | no | Level: RDC | Level: R+1 | 37.1563 | 10152 | 8.54595 | 452492 | ThisIsExisting
452555 | RDC | Core Face: Exterior | 0 | no | Level: RDC | Level: R+1 | 15.6831 | 4300 | 3.60711 | 452555 | ThisIsExisting
452931 | R+1 | Core Face: Exterior | 0 | no | Level: R+1 | Level: R+2 | 8.3265 | 2160 | 1.91509 | 452931
452932 | R+1 | Core Face: Exterior | 0 | no | Level: R+1 | Level: R+2 | 8.2716 | 2145 | 1.90247 | 452932
452933 | R+1 | Core Face: Exterior | 0 | no | Level: R+1 | Level: R+2 | 37.1563 | 10152 | 8.54595 | 452933
452934 | R+1 | Core Face: Exterior | 0 | no | Level: R+1 | Level: R+2 | 15.7563 | 4320 | 3.62395 | 452934
452942 | R+2 | Core Face: Exterior | 140 | no | Level: R+2 | Level: TOITURE | 8.3265 | 2160 | 1.91509 | 452942
452943 | R+2 | Core Face: Exterior | 140 | no | Level: R+2 | Level: TOITURE | 8.2716 | 2145 | 1.90247 | 452943
452944 | R+2 | Core Face: Exterior | 140 | no | Level: R+2 | Level: TOITURE | 37.1563 | 10152 | 8.54595 | 452944
452945 | R+2 | Core Face: Exterior | 140 | no | Level: R+2 | Level: TOITURE | 14.9145 | 4320 | 3.43033 | 452945
452962 | RDC | Core Face: Exterior | 0 | no | Level: RDC | Level: R+1 | 8.2716 | 2160 | 1.90247 | 452962
452963 | RDC | Core Face: Exterior | 0 | no | Level: RDC | Level: R+1 | 8.2716 | 2145 | 1.90247 | 452963
452964 | RDC | Core Face: Exterior | 0 | no | Level: RDC | Level: R+1 | 54.2938 | 14949.4 | 12.4876 | 452964
452965 | RDC | Core Face: Exterior | 0 | no | Level: RDC | Level: R+1 | 15.6099 | 4305 | 3.59028 | 452965
452966 | R+1 | Core Face: Exterior | 0 | no | Level: R+1 | Level: R+2 | 7.4847 | 2160 | 1.72148 | 452966
452967 | R+1 | Core Face: Exterior | 0 | no | Level: R+1 | Level: R+2 | 8.2716 | 2145 | 1.90247 | 452967
452968 | R+1 | Core Face: Exterior | 0 | no | Level: R+1 | Level: R+2 | 37.1563 | 10152 | 8.54595 | 452968
452969 | R+1 | Core Face: Exterior | 0 | no | Level: R+1 | Level: R+2 | 14.7681 | 4305 | 3.39666 | 452969
452970 | R+2 | Core Face: Exterior | 140 | no | Level: R+2 | Level: TOITURE | 7.4847 | 2160 | 1.72148 | 452970
452971 | R+2 | Core Face: Exterior | 140 | no | Level: R+2 | Level: TOITURE | 8.2716 | 2145 | 1.90247 | 452971
452972 | R+2 | Core Face: Exterior | 140 | no | Level: R+2 | Level: TOITURE | 37.1563 | 10152 | 8.54595 | 452972
452973 | R+2 | Core Face: Exterior | 140 | no | Level: R+2 | Level: TOITURE | 14.7681 | 4305 | 3.39666 | 452973
453133 | RDC | Core Face: Exterior | 0 | no | Level: RDC | Level: R+1 | 15.6099 | 4265 | 3.59028 | 453133
453226 | RDC | Core Face: Exterior | 0 | no | Level: RDC | Level: R+1 | 15.4722 | 4457.38 | 3.55861 | 453226
453335 | RDC | Core Face: Exterior | 0 | no | Level: RDC | Level: R+1 | 14.7681 | 4265 | 3.39666 | 453335
453385 | RDC | Core Face: Exterior | 0 | no | Level: RDC | Level: R+1 | 8.6742 | 2600 | 1.99507 | 453385
453442 | R+1 | Core Face: Exterior | 0 | no | Level: R+1 | Level: R+2 | 15.6099 | 4305 | 3.59028 | 453442
453443 | R+1 | Core Face: Exterior | 0 | no | Level: R+1 | Level: R+2 | 16.37 | 4472.68 | 3.7651 | 453443
453444 | R+1 | Core Face: Exterior | 0 | no | Level: R+1 | Level: R+2 | 15.6648 | 4320 | 3.6029 | 453444
453445 | R+1 | Core Face: Exterior | 0 | no | Level: R+1 | Level: R+2 | 15.4722 | 4457.38 | 3.55861 | 453445
453446 | R+1 | Core Face: Exterior | 0 | no | Level: R+1 | Level: R+2 | 14.823 | 4280 | 3.40929 | 453446
453447 | R+1 | Core Face: Exterior | 0 | no | Level: R+1 | Level: R+2 | 8.6742 | 2600 | 1.99507 | 453447
453450 | R+2 | Core Face: Exterior | 140 | no | Level: R+2 | Level: TOITURE | 15.6099 | 4305 | 3.59028 | 453450
453451 | R+2 | Core Face: Exterior | 140 | no | Level: R+2 | Level: TOITURE | 16.37 | 4472.68 | 3.7651 | 453451
453452 | R+2 | Core Face: Exterior | 140 | no | Level: R+2 | Level: TOITURE | 15.6648 | 4320 | 3.6029 | 453452
453453 | R+2 | Core Face: Exterior | 140 | no | Level: R+2 | Level: TOITURE | 15.4722 | 4457.38 | 3.55861 | 453453
453454 | R+2 | Core Face: Exterior | 140 | no | Level: R+2 | Level: TOITURE | 14.823 | 4280 | 3.40929 | 453454
453455 | R+2 | Core Face: Exterior | 140 | no | Level: R+2 | Level: TOITURE | 8.6742 | 2600 | 1.99507 | 453455
523201 | RDC | Core Face: Exterior | 0 | no | Level: RDC | Level: R+1 | 15.738 | 4300 | 3.61974 | 453133 | ThisIsExisting
523263 | RDC | Core Face: Exterior | 0 | no | Level: RDC | Level: R+1 | 17.1566 | 4802.59 | 3.94601 |  | ThisIsExisting
523453 | RDC | Core Face: Exterior | 0 | no | Level: RDC | Level: R+1 | 14.8962 | 4300 | 3.42613 |  | ThisIsExisting
523507 | RDC | Core Face: Exterior | 0 | no | Level: RDC | Level: R+1 | 15.4722 | 4457.38 | 3.55861 |  | ThisIsExisting
524341 | RDC | Wall Centerline | 0 | no | Level: RDC | Level: R+1 | 36.3072 | 10150 | 8.35066 |  | ThisIsExisting
524595 | RDC | Core Face: Exterior | 0 | yes | Level: RDC | Level: R+1 | 43.0621 | 12313.9 | 9.90428 |  | ThisIsExisting
524967 | RDC | Core Face: Exterior | 0 | no | Level: RDC | Level: R+1 | 44.6886 | 12325 | 10.2784 |  | ThisIsExisting
536150 | R+1 | Core Face: Exterior | 0 | no | Level: R+1 | Level: R+2 | 38.796 | 10715 | 8.92308 |  | ThisIsExisting
536269 | R+1 | Core Face: Exterior | 0 | no | Level: R+1 | Level: R+2 | 14.9694 | 4320 | 3.44296 |  | ThisIsExisting
536346 | R+1 | Core Face: Exterior | 0 | no | Level: R+1 | Level: R+2 | 34.4589 | 9415 | 7.92555 |  | ThisIsExisting
536411 | R+1 | Core Face: Exterior | 0 | no | Level: R+1 | Level: R+2 | 14.9694 | 4320 | 3.44296 |  | ThisIsExisting
536557 | R+1 | Core Face: Exterior | 0 | no | Level: R+1 | Level: R+2 | 14.9694 | 4320 | 3.44296 |  | ThisIsExisting
536661 | R+1 | Core Face: Exterior | 0 | no | Level: R+1 | Level: R+2 | 21.5829 | 5896.96 | 4.96406 |  | ThisIsExisting
536781 | R+1 | Core Face: Exterior | 0 | no | Level: R+1 | Level: R+2 | 15.8112 | 4320 | 3.63658 |  | ThisIsExisting
537011 | R+1 | Core Face: Exterior | 0 | no | Level: R+1 | Level: R+2 | 17.2835 | 4952.26 | 3.9752 |  | ThisIsExisting
537803 | R+2 | Core Face: Exterior | 140 | no | Level: R+2 | Level: TOITURE | 15.7563 | 4320 | 3.62395 | 452934
537804 | R+2 | Core Face: Exterior | 140 | no | Level: R+2 | Level: TOITURE | 38.796 | 10715 | 8.92308 |  | ThisIsExisting
537805 | R+2 | Core Face: Exterior | 140 | no | Level: R+2 | Level: TOITURE | 14.9694 | 4320 | 3.44296 |  | ThisIsExisting
537806 | R+2 | Core Face: Exterior | 140 | no | Level: R+2 | Level: TOITURE | 34.4589 | 9415 | 7.92555 |  | ThisIsExisting
537807 | R+2 | Core Face: Exterior | 140 | no | Level: R+2 | Level: TOITURE | 14.9694 | 4320 | 3.44296 |  | ThisIsExisting
537808 | R+2 | Core Face: Exterior | 140 | no | Level: R+2 | Level: TOITURE | 14.9694 | 4320 | 3.44296 |  | ThisIsExisting
537809 | R+2 | Core Face: Exterior | 140 | no | Level: R+2 | Level: TOITURE | 21.5829 | 5896.96 | 4.96406 |  | ThisIsExisting
537810 | R+2 | Core Face: Exterior | 140 | no | Level: R+2 | Level: TOITURE | 15.8112 | 4320 | 3.63658 |  | ThisIsExisting
537811 | R+2 | Core Face: Exterior | 140 | no | Level: R+2 | Level: TOITURE | 17.2835 | 4952.26 | 3.9752 |  | ThisIsExisting
538027 | R+1 | Core Face: Exterior | 0 | no | Level: R+1 | Level: R+2 | 43.1221 | 11782 | 9.91809 |  | ThisIsExisting
538074 | R+1 | Core Face: Exterior | 0 | no | Level: R+1 | Level: R+2 | 43.1221 | 11782 | 9.91809 |  | ThisIsExisting
538094 | R+2 | Core Face: Exterior | 140 | no | Level: R+2 | Level: TOITURE | 43.1221 | 11782 | 9.91809 |  | ThisIsExisting
538095 | R+2 | Core Face: Exterior | 140 | no | Level: R+2 | Level: TOITURE | 43.1221 | 11782 | 9.91809 |  | ThisIsExisting
542646 | R+1 | Finish Face: Exterior | 0 | no | Level: R+1 | Level: R+2 | 15.8112 | 4205 | 3.63658 |  | ThisIsExisting
543217 | R+1 | Finish Face: Exterior | 0 | no | Level: R+1 | Level: R+2 | 37.1632 | 10153.9 | 8.54754 |  | ThisIsExisting
543271 | R+1 | Finish Face: Exterior | 0 | no | Level: R+1 | Level: R+2 | 43.7846 | 12193 | 10.0705 |  | ThisIsExisting
544892 | R+1 | Finish Face: Exterior | 0 | no | Level: R+1 | Level: R+2 | 36.3072 | 10150 | 8.35066 |  | ThisIsExisting
548981 | R+2 | Finish Face: Exterior | 140 | no | Level: R+2 | Level: TOITURE | 44.2055 | 12193 | 10.1673 |  | ThisIsExisting
548982 | R+2 | Finish Face: Exterior | 140 | no | Level: R+2 | Level: TOITURE | 36.3072 | 10150 | 8.35066 |  | ThisIsExisting
549004 | R+2 | Finish Face: Exterior | 140 | no | Level: R+2 | Level: TOITURE | 37.1632 | 10153.9 | 8.54754 |  | ThisIsExisting
549084 | RDC | Wall Centerline | 0 | no | Level: RDC | Level: R+1 | 36.3072 | 10150 | 8.35066 |  | ThisIsExisting
584031 | RDC | Core Face: Exterior | 0 | no | Level: RDC | Level: R+1 | 16.0213 | 4592.4 | 3.68489 |  | ThisIsExisting
584137 | R+1 | Core Face: Exterior | 0 | no | Level: R+1 | Level: R+2 | 16.0213 | 4592.4 | 3.68489 |  | ThisIsExisting
584140 | R+2 | Core Face: Exterior | 140 | no | Level: R+2 | Level: TOITURE | 16.8082 | 4592.4 | 3.86588 |  | ThisIsExisting

# IfcWallStandardCase: Basic Wall:Mur430PentureBlanche (12)
Type - PredefinedType: STANDARD; Material: Paint - White Lining 15 mm, Concrete - Precast Concrete - 35 MPa 400 mm, Paint - White Lining 15 mm
Type - Analytical Properties - Roughness: 3; Absorptance: 0.7
Type - Construction - Wrapping at Inserts: Both; Function: Exterior; Width: 430 mm
Type - Graphics - Coarse Scale Fill Pattern: <Solid fill>; Coarse Scale Fill Color: 12632256
Type - Identity Data - Keynote: F10; Type Name: Mur430PentureBlanche
Type - Materials and Finishes - Structural Material: Concrete - Precast Concrete - 35 MPa
Type - Other - Category: Walls; Family Name: Basic Wall
Type - Pset_ElementShading - Roughness: 914.4 mm
Type - Pset_ProductRequirements - Category: Walls
Type - Pset_QuantityTakeOff - Reference: Mur430PentureBlanche
Type - Pset_ReinforcementBarPitchOfWall - Reference: Mur430PentureBlanche
Type - Pset_WallCommon - IsExternal: no; Reference: Mur430PentureBlanche
Constraints - Base Extension Distance: 0 mm; Base is Attached: no; Base Offset: 0 mm; Cross-Section: Vertical; Related to Mass: no; Room Bounding: yes; Top Extension Distance: 0 mm; Top is Attached: no; Location Line: Core Centerline; Unconnected Height: 3660 mm
Dimensions - Area: 5.45341 m2; Length: 1490 mm; Volume: 2.34496 m3
Other - Family: Basic Wall: Mur430PentureBlanche; Family and Type: Basic Wall: Mur430PentureBlanche; Type: Basic Wall: Mur430PentureBlanche; Type Id: Basic Wall: Mur430PentureBlanche
Phasing - Phase Created: Existing
Structural - Enable Analytical Model: no; Structural: no; Structural Usage: Non-bearing
Pset_QuantityTakeOff - sets with these values: 2
Pset_WallCommon - ExtendToStructure: no; LoadBearing: no; IsExternal: yes
Name (Basic Wall:Mur430PentureBlanche:...) | In | Top Offset (mm) | Base Constraint | Top Constraint | ElementID
451717 | RDC | 0 | Level: RDC | Level: R+1 | 451717
451767 | RDC | 0 | Level: RDC | Level: R+1 | 451767
452148 | R+1 | 0 | Level: R+1 | Level: R+2 | 452148
452149 | R+1 | 0 | Level: R+1 | Level: R+2 | 452149
452152 | R+2 | 140 | Level: R+2 | Level: TOITURE | 452152
452153 | R+2 | 140 | Level: R+2 | Level: TOITURE | 452153
452175 | RDC | 0 | Level: RDC | Level: R+1 | 452175
452176 | RDC | 0 | Level: RDC | Level: R+1 | 452176
452177 | R+1 | 0 | Level: R+1 | Level: R+2 | 452177
452178 | R+1 | 0 | Level: R+1 | Level: R+2 | 452178
452179 | R+2 | 140 | Level: R+2 | Level: TOITURE | 452179
452180 | R+2 | 140 | Level: R+2 | Level: TOITURE | 452180

# IfcWallStandardCase: Basic Wall:Wall-Fnd_200interior (7)
In: R-1
Type - PredefinedType: STANDARD; Material: Concrete - Cast-in-Place Concrete 200 mm
Type - Analytical Properties - Absorptance: 0.7; Roughness: 3
Type - Construction - Function: Interior; Width: 200 mm; Wrapping at Inserts: Both
Type - Graphics - Coarse Scale Fill Color: 12632256; Coarse Scale Fill Pattern: <Solid fill>
Type - Identity Data - Keynote: F10; Type Name: Wall-Fnd_200interior
Type - Materials and Finishes - Structural Material: Concrete - Cast-in-Place Concrete
Type - Other - Category: Walls; Family Name: Basic Wall
Type - Pset_ElementShading - Roughness: 914.4 mm
Type - Pset_ProductRequirements - Category: Walls
Type - Pset_QuantityTakeOff - Reference: Wall-Fnd_200interior
Type - Pset_ReinforcementBarPitchOfWall - Reference: Wall-Fnd_200interior
Type - Pset_WallCommon - Reference: Wall-Fnd_200interior; IsExternal: no
Constraints - Base Constraint: Level: R-1; Base Extension Distance: 0 mm; Base is Attached: no; Base Offset: 0 mm; Cross-Section: Vertical; Location Line: Core Face: Exterior; Related to Mass: no; Room Bounding: yes; Top Constraint: Level: RDC; Top Extension Distance: 0 mm
Other - Family: Basic Wall: Wall-Fnd_200interior; Family and Type: Basic Wall: Wall-Fnd_200interior; Type: Basic Wall: Wall-Fnd_200interior; Type Id: Basic Wall: Wall-Fnd_200interior
Phasing - Phase Created: Existing
Structural - Enable Analytical Model: no; Structural: no; Structural Usage: Non-bearing
Pset_QuantityTakeOff - sets with these values: 2
Pset_WallCommon - LoadBearing: no
Name (Basic Wall:Wall-Fnd_200interior:...) | Top is Attached = ExtendToStructure | Top Offset (mm) | Unconnected Height (mm) | Area (m2) | Length (mm) | Volume (m3) | ElementID
383282 | no | 200 | 3700 | 30.8395 | 8550 | 6.1679 | 383282 | Identity Data - Comments: ThisIsExisting
383382 | no | 0 | 3500 | 35.63 | 10180 | 7.126 | 383382
383433 | no | 0 | 3500 | 15.12 | 4635 | 3.024 | 383433
383479 | yes | 0 | 3500 | 14.5584 | 4635 | 2.91168 | 383479
386321 | no | 0 | 3500 | 34.825 | 10380 | 6.965 | 386321
389431 | yes | 0 | 3500 | 34.3066 | 10180 | 6.86132 | 389431
389433 | no | 0 | 3500 | 15.12 | 4635 | 3.024 | 389433

# IfcWallStandardCase: Basic Wall:Wall-Int 100 (148)
Type - PredefinedType: STANDARD; Material: Paint - White Lining 3 mm, Concrete Masonry Units 94 mm, Paint - White Lining 3 mm
Type - Analytical Properties - Roughness: 3; Absorptance: 0.7; Heat Transfer Coefficient (U): 13.8298; Thermal Mass: 13.2041; Thermal Resistance (R): 0.0723077
Type - Construction - Function: Interior; Wrapping at Inserts: Both; Width: 100 mm
Type - Graphics - Coarse Scale Fill Pattern: <Solid fill>; Coarse Scale Fill Color: 12632256
Type - Identity Data - Type Name: Wall-Int 100
Type - Materials and Finishes - Structural Material: Concrete Masonry Units
Type - Other - Category: Walls; Family Name: Basic Wall
Type - Pset_ElementShading - Roughness: 914.4 mm
Type - Pset_ProductRequirements - Category: Walls
Type - Pset_QuantityTakeOff - Reference: Wall-Int 100
Type - Pset_ReinforcementBarPitchOfWall - Reference: Wall-Int 100
Type - Pset_WallCommon - IsExternal: no; Reference: Wall-Int 100; ThermalTransmittance: 13.8298 kg/K/s3
Constraints - Base Extension Distance: 0 mm; Base is Attached: no; Base Offset: 0 mm; Cross-Section: Vertical; Related to Mass: no; Room Bounding: yes; Top Extension Distance: 0 mm
Other - Family: Basic Wall: Wall-Int 100; Family and Type: Basic Wall: Wall-Int 100; Type: Basic Wall: Wall-Int 100; Type Id: Basic Wall: Wall-Int 100
Phasing - Phase Created: Existing
Structural - Enable Analytical Model: no; Structural: no; Structural Usage: Non-bearing
Pset_QuantityTakeOff - sets with these values: 2
Pset_WallCommon - LoadBearing: no
Name (Basic Wall:Wall-Int 100:...) | In | Base Constraint | Location Line | Top Constraint | Top is Attached = ExtendToStructure | Top Offset (mm) | Unconnected Height (mm) | Area (m2) | Length (mm) | Volume (m3) | Comments
386703 | R-1 | Level: R-1 | Core Face: Exterior | Level: RDC | no | 0 | 3500 | 34.8845 | 10067 | 3.48845 | Other - ElementID: 386703
386773 | R-1 | Level: R-1 | Core Face: Exterior | Level: RDC | yes | 0 | 3500 | 15.3202 | 4808 | 1.53202 | Other - ElementID: 386773
386871 | R-1 | Level: R-1 | Core Face: Exterior | Level: RDC | no | 0 | 3500 | 14.315 | 4090 | 1.4315 | Other - ElementID: 386871
387571 | R-1 | Level: R-1 | Core Centerline | Level: RDC | no | 0 | 3500 | 13.396 | 3920 | 1.3396 | Other - ElementID: 387571
387615 | R-1 | Level: R-1 | Core Centerline | Level: RDC | no | 0 | 3500 | 10.5689 | 3159.69 | 1.05689 | Other - ElementID: 387615
387648 | R-1 | Level: R-1 | Core Centerline | Level: RDC | no | 0 | 3500 | 12.696 | 3920 | 1.2696 | Other - ElementID: 387648
387686 | R-1 | Level: R-1 | Core Centerline | Level: RDC | no | 0 | 3500 | 10.5689 | 3159.69 | 1.05689 | Other - ElementID: 387686
387788 | R-1 | Level: R-1 | Core Centerline | Level: RDC | no | 0 | 3500 | 3.325 | 1000 | 0.3325 | Other - ElementID: 387788
387817 | R-1 | Level: R-1 | Core Centerline | Level: RDC | no | 0 | 3500 | 7.105 | 2170 | 0.7105 | Other - ElementID: 387817
387846 | R-1 | Level: R-1 | Core Centerline | Level: RDC | no | 0 | 3500 | 3.15 | 1000 | 0.315 | Other - ElementID: 387846
388047 | R-1 | Level: R-1 | Core Centerline | Level: RDC | no | 0 | 3500 | 3.12822 | 993.778 | 0.312822 | Other - ElementID: 388047
388076 | R-1 | Level: R-1 | Core Centerline | Level: RDC | no | 0 | 3500 | 3.12822 | 993.778 | 0.312822 | Other - ElementID: 388076
389471 | R-1 | Level: R-1 | Core Centerline | Level: RDC | no | 0 | 3500 | 13.396 | 3920 | 1.3396 | Other - ElementID: 389471
389472 | R-1 | Level: R-1 | Core Centerline | Level: RDC | no | 0 | 3500 | 10.5689 | 3159.69 | 1.05689 | Other - ElementID: 389472
389473 | R-1 | Level: R-1 | Core Centerline | Level: RDC | no | 0 | 3500 | 12.696 | 3920 | 1.2696 | Other - ElementID: 389473
389474 | R-1 | Level: R-1 | Core Centerline | Level: RDC | no | 0 | 3500 | 10.5689 | 3159.69 | 1.05689 | Other - ElementID: 389474
389475 | R-1 | Level: R-1 | Core Centerline | Level: RDC | no | 0 | 3500 | 3.325 | 1000 | 0.3325 | Other - ElementID: 389475
389476 | R-1 | Level: R-1 | Core Centerline | Level: RDC | no | 0 | 3500 | 7.105 | 2170 | 0.7105 | Other - ElementID: 389476
389477 | R-1 | Level: R-1 | Core Centerline | Level: RDC | no | 0 | 3500 | 3.15 | 1000 | 0.315 | Other - ElementID: 389477
389478 | R-1 | Level: R-1 | Core Centerline | Level: RDC | no | 0 | 3500 | 3.12822 | 993.778 | 0.312822 | Other - ElementID: 389478
389479 | R-1 | Level: R-1 | Core Centerline | Level: RDC | no | 0 | 3500 | 3.12822 | 993.778 | 0.312822 | Other - ElementID: 389479
525360 | RDC | Level: RDC | Core Face: Exterior | Level: R+1 | yes | 0 | 3660 | 4.6908 | 10272.6 | 0.46908 | ThisIsExisting
533480 | RDC | Level: RDC | Core Face: Exterior | Level: R+1 | yes | 0 | 3660 | 4.68322 | 10272.6 | 0.468322 | ThisIsExisting
535950 | R+1 | Level: R+1 | Core Face: Exterior | Level: R+2 | no | 0 | 3660 | 1.393 | 9950 | 0.1393 | ThisIsExisting
535980 | R+2 | Level: R+2 | Core Face: Exterior | Level: TOITURE | no | 140 | 3660 | 1.393 | 9950 | 0.1393 | ThisIsExisting
540834 | R+1 | Level: R+1 | Finish Face: Exterior | Level: R+2 | no | 0 | 3660 | 36.4207 | 9951 | 3.64207 | ThisIsExisting
540879 | R+1 | Level: R+1 | Finish Face: Exterior | Level: R+2 | no | 0 | 3660 | 36.4207 | 9951 | 3.64207 | ThisIsExisting
540899 | R+2 | Level: R+2 | Finish Face: Exterior | Level: TOITURE | no | 140 | 3660 | 37.2039 | 10165 | 3.72039 | ThisIsExisting
540900 | R+2 | Level: R+2 | Finish Face: Exterior | Level: TOITURE | no | 140 | 3660 | 37.2039 | 10165 | 3.72039 | ThisIsExisting
541012 | R+1 | Level: R+1 | Finish Face: Exterior | Level: R+2 | no | 0 | 3660 | 36.417 | 9950 | 3.6417 | ThisIsExisting
541109 | R+1 | Level: R+1 | Finish Face: Exterior | Level: R+2 | no | 0 | 3660 | 36.6073 | 10002 | 3.66073 | ThisIsExisting
541235 | R+1 | Level: R+1 | Finish Face: Exterior | Level: R+2 | no | 0 | 3660 | 36.434 | 9954.64 | 3.6434 | ThisIsExisting
541359 | R+1 | Level: R+1 | Finish Face: Exterior | Level: R+2 | no | 0 | 3660 | 36.6243 | 10006.6 | 3.66243 | ThisIsExisting
541402 | R+1 | Level: R+1 | Finish Face: Exterior | Level: R+2 | no | 0 | 3660 | 5.13132 | 1402 | 0.513132 | ThisIsExisting
541672 | R+1 | Level: R+1 | Finish Face: Exterior | Level: R+2 | no | 0 | 3660 | 36.6146 | 10004 | 3.66146 | ThisIsNew
541777 | R+1 | Level: R+1 | Finish Face: Exterior | Level: R+2 | no | 0 | 3660 | 5.124 | 1400 | 0.5124 | ThisIsExisting
541825 | R+1 | Level: R+1 | Finish Face: Exterior | Level: R+2 | no | 0 | 3660 | 5.124 | 1400 | 0.5124 | ThisIsExisting
541976 | R+1 | Level: R+1 | Finish Face: Exterior | Level: R+2 | no | 0 | 3660 | 36.5268 | 9980 | 3.65268 | ThisIsExisting
542047 | R+1 | Level: R+1 | Finish Face: Exterior | Level: R+2 | no | 0 | 3660 | 36.4207 | 9951 | 3.64207 | ThisIsExisting
542151 | R+1 | Level: R+1 | Finish Face: Exterior | Level: R+2 | no | 0 | 3660 | 36.4243 | 9952 | 3.64243 | ThisIsExisting
542233 | R+1 | Level: R+1 | Finish Face: Exterior | Level: R+2 | no | 0 | 3660 | 36.4243 | 9952 | 3.64243 | ThisIsExisting
542339 | R+1 | Level: R+1 | Finish Face: Exterior | Level: R+2 | no | 0 | 3660 | 36.4243 | 9952 | 3.64243 | ThisIsExisting
542450 | R+1 | Level: R+1 | Finish Face: Exterior | Level: R+2 | no | 0 | 3660 | 36.417 | 9950 | 3.6417 | ThisIsExisting
542534 | R+1 | Level: R+1 | Finish Face: Exterior | Level: R+2 | yes | 0 | 3660 | 35.1306 | 9952 | 3.51306 | ThisIsExisting
542584 | R+1 | Level: R+1 | Finish Face: Exterior | Level: R+2 | no | 0 | 3660 | 5.13864 | 1404 | 0.513864 | ThisIsExisting
543034 | R+1 | Level: R+1 | Finish Face: Exterior | Level: R+2 | no | 0 | 3660 | 6.63558 | 2043 | 0.663558 | ThisIsExisting
543576 | R+1 | Level: R+1 | Finish Face: Exterior | Level: R+2 | no | 0 | 3660 | 36.6243 | 10006.6 | 3.66243 | ThisIsExisting
543682 | R+1 | Level: R+1 | Finish Face: Exterior | Level: R+2 | no | 0 | 3660 | 36.6146 | 10004 | 3.66146 | ThisIsExisting
543802 | R+1 | Level: R+1 | Finish Face: Exterior | Level: R+2 | no | 0 | 3660 | 14.9694 | 4320 | 1.49694 | ThisIsExisting
543866 | R+1 | Level: R+1 | Finish Face: Exterior | Level: R+2 | no | 0 | 3660 | 5.856 | 1600 | 0.5856 | ThisIsExisting
543905 | R+1 | Level: R+1 | Finish Face: Exterior | Level: R+2 | no | 0 | 3660 | 5.49 | 1600 | 0.549 | ThisIsExisting
543951 | R+1 | Level: R+1 | Finish Face: Exterior | Level: R+2 | no | 0 | 3660 | 15.5915 | 4259.97 | 1.55915 | ThisIsExisting
544005 | R+1 | Level: R+1 | Finish Face: Exterior | Level: R+2 | no | 0 | 3660 | 6.6978 | 1930 | 0.66978 | ThisIsExisting
544065 | R+1 | Level: R+1 | Finish Face: Exterior | Level: R+2 | no | 0 | 3660 | 6.84283 | 1934.63 | 0.684283 | ThisIsExisting
544106 | R+1 | Level: R+1 | Finish Face: Exterior | Level: R+2 | no | 0 | 3660 | 6.6978 | 1930 | 0.66978 | ThisIsExisting
544156 | R+1 | Level: R+1 | Finish Face: Exterior | Level: R+2 | no | 0 | 3660 | 6.6978 | 1930 | 0.66978 | ThisIsExisting
544236 | R+1 | Level: R+1 | Finish Face: Exterior | Level: R+2 | no | 0 | 3660 | 5.49 | 1600 | 0.549 | ThisIsExisting
544362 | R+1 | Level: R+1 | Finish Face: Exterior | Level: R+2 | no | 0 | 3660 | 16.6236 | 4606.96 | 1.66236 | ThisIsExisting
544415 | R+1 | Level: R+1 | Finish Face: Exterior | Level: R+2 | no | 0 | 3660 | 13.799 | 3935.23 | 1.3799 | ThisIsExisting
544478 | R+1 | Level: R+1 | Finish Face: Exterior | Level: R+2 | no | 0 | 3660 | 5.8194 | 1590 | 0.58194 | ThisIsExisting
544522 | R+1 | Level: R+1 | Finish Face: Exterior | Level: R+2 | no | 0 | 3660 | 6.65247 | 1917.61 | 0.665247 | ThisIsExisting
544596 | R+1 | Level: R+1 | Finish Face: Exterior | Level: R+2 | no | 0 | 3660 | 5.4534 | 1590 | 0.54534 | ThisIsExisting
544651 | R+1 | Level: R+1 | Finish Face: Exterior | Level: R+2 | no | 0 | 3660 | 6.87948 | 1944.64 | 0.687948 | ThisIsExisting
544690 | R+1 | Level: R+1 | Finish Face: Exterior | Level: R+2 | no | 0 | 3660 | 6.64945 | 1916.79 | 0.664945 | ThisIsExisting
545965 | R+2 | Level: R+2 | Finish Face: Exterior | Level: TOITURE | no | 0 | 3520 | 35.2 | 10000 | 3.52 | ThisIsExisting
546081 | R+2 | Level: R+2 | Finish Face: Exterior | Level: TOITURE | no | 0 | 3520 | 35.024 | 9950 | 3.5024 | ThisIsExisting
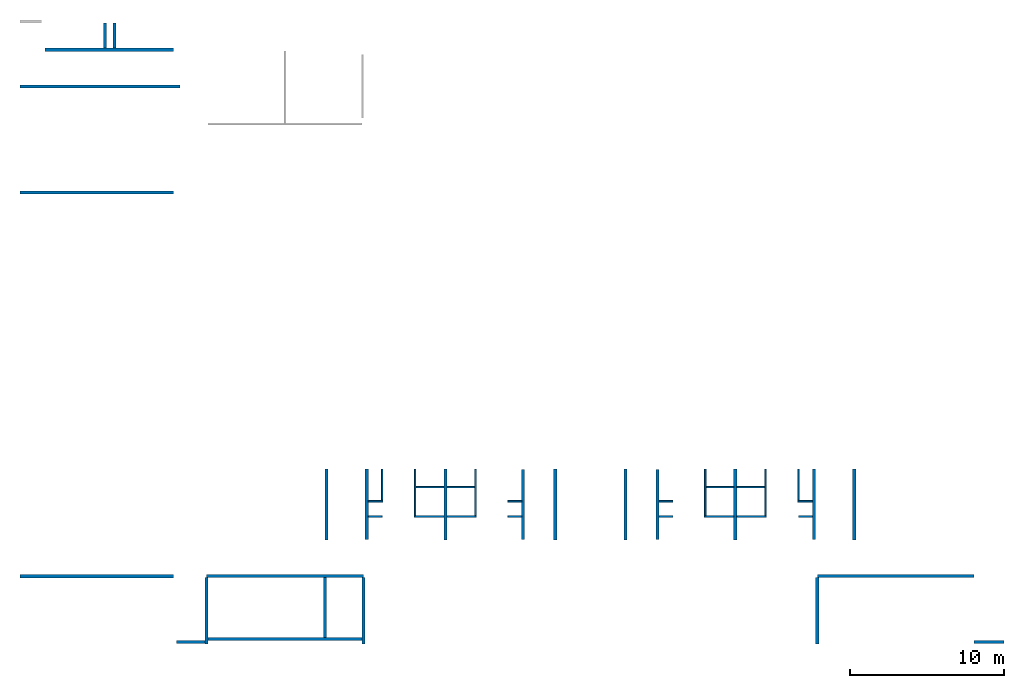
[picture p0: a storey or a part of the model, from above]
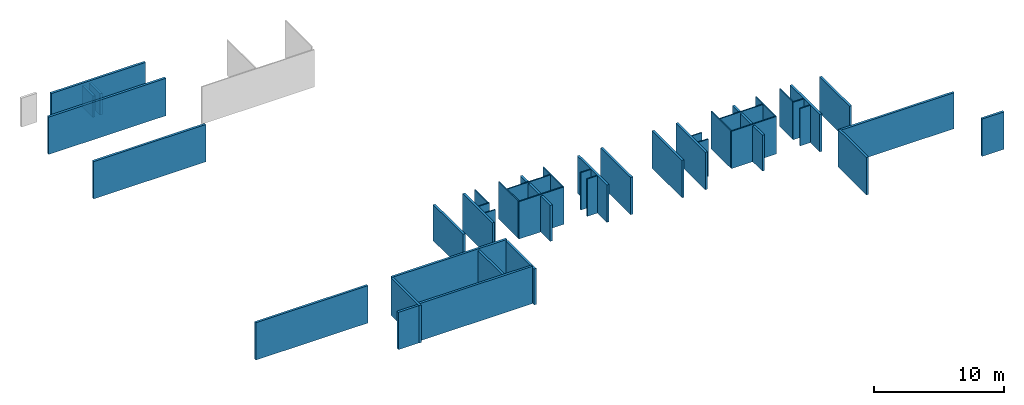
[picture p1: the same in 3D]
Properties of the parts of a building model (IFC2X3), part 3 of 3

# IfcWallStandardCase: Basic Wall:Wall-Int 100 (148)
Name (Basic Wall:Wall-Int 100:...) | In | Base Constraint | Location Line | Top Constraint | Top is Attached = ExtendToStructure | Top Offset (mm) | Unconnected Height (mm) | Area (m2) | Length (mm) | Volume (m3) | Comments
546194 | R+2 | Level: R+2 | Finish Face: Exterior | Level: TOITURE | no | 0 | 3520 | 35.0381 | 9954 | 3.50381 | ThisIsExisting
546277 | R+2 | Level: R+2 | Finish Face: Exterior | Level: TOITURE | no | 0 | 3520 | 35.031 | 9952 | 3.5031 | ThisIsExisting
546352 | R+2 | Level: R+2 | Finish Face: Exterior | Level: TOITURE | no | 0 | 3520 | 35.0802 | 9965.96 | 3.50802 | ThisIsExisting
546404 | R+2 | Level: R+2 | Finish Face: Exterior | Level: TOITURE | no | 0 | 3520 | 35.024 | 9950 | 3.5024 | ThisIsExisting
546457 | R+2 | Level: R+2 | Finish Face: Exterior | Level: TOITURE | no | 0 | 3520 | 35.0381 | 9954 | 3.50381 | ThisIsExisting
546553 | R+2 | Level: R+2 | Finish Face: Exterior | Level: TOITURE | no | 0 | 3520 | 35.0346 | 9953 | 3.50346 | ThisIsExisting
546665 | R+2 | Level: R+2 | Finish Face: Exterior | Level: TOITURE | no | 0 | 3520 | 35.0732 | 9963.96 | 3.50732 | ThisIsExisting
546817 | R+2 | Level: R+2 | Finish Face: Exterior | Level: TOITURE | no | 0 | 3520 | 35.024 | 9950 | 3.5024 | ThisIsExisting
546908 | R+2 | Level: R+2 | Finish Face: Exterior | Level: TOITURE | no | 0 | 3520 | 35.031 | 9952 | 3.5031 | ThisIsExisting
547004 | R+2 | Level: R+2 | Finish Face: Exterior | Level: TOITURE | no | 0 | 3520 | 35.031 | 9952 | 3.5031 | ThisIsExisting
547088 | R+2 | Level: R+2 | Finish Face: Exterior | Level: TOITURE | no | 0 | 3520 | 35.031 | 9952 | 3.5031 | ThisIsExisting
547176 | R+2 | Level: R+2 | Finish Face: Exterior | Level: TOITURE | no | 0 | 3520 | 35.024 | 9950 | 3.5024 | ThisIsExisting
547258 | R+2 | Level: R+2 | Finish Face: Exterior | Level: TOITURE | no | 0 | 3520 | 35.0381 | 9954 | 3.50381 | ThisIsExisting
547327 | R+2 | Level: R+2 | Finish Face: Exterior | Level: TOITURE | no | 0 | 3520 | 35.024 | 9950 | 3.5024 | ThisIsExisting
547394 | R+2 | Level: R+2 | Finish Face: Exterior | Level: TOITURE | no | 0 | 3520 | 4.93504 | 1402 | 0.493504 | ThisIsExisting
547444 | R+2 | Level: R+2 | Finish Face: Exterior | Level: TOITURE | no | 0 | 3520 | 4.93504 | 1402 | 0.493504 | ThisIsExisting
547496 | R+2 | Level: R+2 | Finish Face: Exterior | Level: TOITURE | no | 0 | 3520 | 4.93504 | 1402 | 0.493504 | ThisIsExisting
547648 | R+2 | Level: R+2 | Finish Face: Exterior | Level: TOITURE | no | 140 | 3660 | 14.9694 | 4320 | 1.49694 | ThisIsExisting
547649 | R+2 | Level: R+2 | Finish Face: Exterior | Level: TOITURE | no | 140 | 3660 | 5.856 | 1600 | 0.5856 | ThisIsExisting
547650 | R+2 | Level: R+2 | Finish Face: Exterior | Level: TOITURE | no | 140 | 3660 | 5.49 | 1600 | 0.549 | ThisIsExisting
547651 | R+2 | Level: R+2 | Finish Face: Exterior | Level: TOITURE | no | 140 | 3660 | 15.5915 | 4259.97 | 1.55915 | ThisIsExisting
547652 | R+2 | Level: R+2 | Finish Face: Exterior | Level: TOITURE | no | 140 | 3660 | 6.6978 | 1930 | 0.66978 | ThisIsExisting
547653 | R+2 | Level: R+2 | Finish Face: Exterior | Level: TOITURE | no | 140 | 3660 | 6.84283 | 1934.63 | 0.684283 | ThisIsExisting
547654 | R+2 | Level: R+2 | Finish Face: Exterior | Level: TOITURE | no | 140 | 3660 | 6.6978 | 1930 | 0.66978 | ThisIsExisting
547655 | R+2 | Level: R+2 | Finish Face: Exterior | Level: TOITURE | no | 140 | 3660 | 6.6978 | 1930 | 0.66978 | ThisIsExisting
547656 | R+2 | Level: R+2 | Finish Face: Exterior | Level: TOITURE | no | 140 | 3660 | 5.49 | 1600 | 0.549 | ThisIsExisting
547670 | R+2 | Level: R+2 | Finish Face: Exterior | Level: TOITURE | no | 140 | 3660 | 16.6236 | 4606.96 | 1.66236 | ThisIsExisting
547671 | R+2 | Level: R+2 | Finish Face: Exterior | Level: TOITURE | no | 140 | 3660 | 13.799 | 3935.23 | 1.3799 | ThisIsExisting
547672 | R+2 | Level: R+2 | Finish Face: Exterior | Level: TOITURE | no | 140 | 3660 | 5.8194 | 1590 | 0.58194 | ThisIsExisting
547673 | R+2 | Level: R+2 | Finish Face: Exterior | Level: TOITURE | no | 140 | 3660 | 6.65247 | 1917.61 | 0.665247 | ThisIsExisting
547674 | R+2 | Level: R+2 | Finish Face: Exterior | Level: TOITURE | no | 140 | 3660 | 5.4534 | 1590 | 0.54534 | ThisIsExisting
547675 | R+2 | Level: R+2 | Finish Face: Exterior | Level: TOITURE | no | 140 | 3660 | 6.87948 | 1944.64 | 0.687948 | ThisIsExisting
547676 | R+2 | Level: R+2 | Finish Face: Exterior | Level: TOITURE | no | 140 | 3660 | 6.64945 | 1916.79 | 0.664945 | ThisIsExisting
547722 | R+1 | Level: R+1 | Finish Face: Exterior | Level: R+2 | no | 0 | 3660 | 43.188 | 11800 | 4.3188 | ThisIsExisting
547771 | R+1 | Level: R+1 | Finish Face: Exterior | Level: R+2 | no | 0 | 3660 | 43.1294 | 11784 | 4.31294 | ThisIsExisting
548422 | R+2 | Level: R+2 | Finish Face: Exterior | Level: TOITURE | no | 0 | 3520 | 35.031 | 9952 | 3.5031 | ThisIsExisting
548512 | R+2 | Level: R+2 | Finish Face: Exterior | Level: TOITURE | no | 0 | 3520 | 35.031 | 9952 | 3.5031 | ThisIsExisting
548567 | R+2 | Level: R+2 | Finish Face: Exterior | Level: TOITURE | no | 0 | 3520 | 35.031 | 9952 | 3.5031 | ThisIsExisting
548666 | R+2 | Level: R+2 | Finish Face: Exterior | Level: TOITURE | no | 0 | 3520 | 4.94208 | 1404 | 0.494208 | ThisIsExisting
548980 | R+2 | Level: R+2 | Finish Face: Exterior | Level: TOITURE | no | 140 | 3660 | 5.13132 | 1402 | 0.513132 | ThisIsExisting
549003 | R+2 | Level: R+2 | Finish Face: Exterior | Level: TOITURE | no | 140 | 3660 | 36.6 | 10000 | 3.66 | ThisIsExisting
555751 | RDC | Level: RDC | Finish Face: Exterior | Level: R+1 | no | 0 | 3660 | 14.9145 | 4190 | 1.49145 | ThisIsExisting
555842 | RDC | Level: RDC | Finish Face: Exterior | Level: R+1 | no | 0 | 3660 | 7.11138 | 2108 | 0.711138 | ThisIsExisting
555913 | RDC | Level: RDC | Finish Face: Exterior | Level: R+1 | no | 0 | 3660 | 5.13864 | 1404 | 0.513864 | ThisIsExisting
556001 | RDC | Level: RDC | Finish Face: Exterior | Level: R+1 | no | 0 | 3660 | 36.4316 | 9954 | 3.64316 | ThisIsExisting
556080 | RDC | Level: RDC | Finish Face: Exterior | Level: R+1 | no | 0 | 3660 | 6.6978 | 1830 | 0.66978 | ThisIsExisting
556141 | RDC | Level: RDC | Finish Face: Exterior | Level: R+1 | no | 0 | 3660 | 36.4243 | 9952 | 3.64243 | ThisIsExisting
556210 | RDC | Level: RDC | Finish Face: Exterior | Level: R+1 | no | 0 | 3660 | 36.4243 | 9952 | 3.64243 | ThisIsExisting
556269 | RDC | Level: RDC | Finish Face: Exterior | Level: R+1 | no | 0 | 3660 | 5.124 | 1400 | 0.5124 | ThisIsExisting
556340 | RDC | Level: RDC | Finish Face: Exterior | Level: R+1 | no | 0 | 3660 | 23.424 | 6400 | 2.3424 | ThisIsExisting
556393 | RDC | Level: RDC | Finish Face: Exterior | Level: R+1 | no | 0 | 3660 | 5.124 | 1400 | 0.5124 | ThisIsExisting
556478 | RDC | Level: RDC | Finish Face: Exterior | Level: R+1 | no | 0 | 3660 | 14.9694 | 4090 | 1.49694 | ThisIsExisting
556563 | RDC | Level: RDC | Finish Face: Exterior | Level: R+1 | no | 0 | 3660 | 2.56208 | 650.023 | 0.256208 | ThisIsExisting
556621 | RDC | Level: RDC | Finish Face: Exterior | Level: R+1 | no | 0 | 3660 | 25.8213 | 7055.01 | 2.58213 | ThisIsExisting
556658 | RDC | Level: RDC | Finish Face: Exterior | Level: R+1 | no | 0 | 3660 | 2.196 | 650.001 | 0.2196 | ThisIsExisting
556737 | RDC | Level: RDC | Finish Face: Exterior | Level: R+1 | no | 0 | 3660 | 43.188 | 11800 | 4.3188 | ThisIsExisting
556820 | RDC | Level: RDC | Finish Face: Exterior | Level: R+1 | no | 0 | 3660 | 10.0529 | 2846.7 | 1.00529 | ThisIsExisting
556853 | RDC | Level: RDC | Finish Face: Exterior | Level: R+1 | no | 0 | 3660 | 5.124 | 1400 | 0.5124 | ThisIsExisting
556902 | RDC | Level: RDC | Finish Face: Exterior | Level: R+1 | no | 0 | 3660 | 7.48604 | 2145.37 | 0.748604 | ThisIsExisting
556986 | RDC | Level: RDC | Finish Face: Exterior | Level: R+1 | no | 0 | 3660 | 36.4316 | 9954 | 3.64316 | ThisIsExisting
557039 | RDC | Level: RDC | Finish Face: Exterior | Level: R+1 | yes | 0 | 3660 | 35.1318 | 9952.36 | 3.51318 | ThisIsExisting
569137 | R+2 | Level: R+2 | Wall Centerline | Level: TOITURE | no | 0 | 3520 | 0.795608 | 441.025 | 0.0795608 | ThisIsExisting
569276 | R+2 | Level: R+2 | Wall Centerline | Level: TOITURE | no | 0 | 3520 | 0.841192 | 353.975 | 0.0841192 | ThisIsExisting
569416 | R+2 | Level: R+2 | Wall Centerline | Level: TOITURE | no | 0 | 3520 | 0.795608 | 441.025 | 0.0795608 | ThisIsExisting
569417 | R+2 | Level: R+2 | Wall Centerline | Level: TOITURE | no | 0 | 3520 | 0.86006 | 359.335 | 0.086006 | ThisIsExisting
569527 | R+1 | Level: R+1 | Wall Centerline | Level: R+2 | no | -140 | 3520 | 0.795608 | 441.025 | 0.0795608 | ThisIsExisting
569528 | R+1 | Level: R+1 | Wall Centerline | Level: R+2 | no | -140 | 3520 | 0.841192 | 353.975 | 0.0841192 | ThisIsExisting
569556 | R+1 | Level: R+1 | Wall Centerline | Level: R+2 | no | -140 | 3520 | 0.795608 | 441.025 | 0.0795608 | ThisIsExisting
569557 | R+1 | Level: R+1 | Wall Centerline | Level: R+2 | no | -140 | 3520 | 0.86006 | 359.335 | 0.086006 | ThisIsExisting
577543 | RDC | Level: RDC | Core Face: Exterior | Level: R+1 | no | 0 | 3660 | 6.74655 | 1843.32 | 0.674655 | ThisIsExisting
577599 | RDC | Level: RDC | Core Face: Exterior | Level: R+1 | no | 0 | 3660 | 6.6978 | 1830 | 0.66978 | ThisIsExisting
577671 | RDC | Level: RDC | Core Face: Exterior | Level: R+1 | no | 0 | 3660 | 6.74655 | 1843.32 | 0.674655 | ThisIsExisting
577672 | RDC | Level: RDC | Core Face: Exterior | Level: R+1 | no | 0 | 3660 | 6.6978 | 1830 | 0.66978 | ThisIsExisting
577701 | RDC | Level: RDC | Core Face: Exterior | Level: R+1 | no | 0 | 3660 | 6.6978 | 1830 | 0.66978 | ThisIsExisting
577702 | RDC | Level: RDC | Core Face: Exterior | Level: R+1 | no | 0 | 3660 | 6.74655 | 1843.32 | 0.674655 | ThisIsExisting
577703 | RDC | Level: RDC | Core Face: Exterior | Level: R+1 | no | 0 | 3660 | 6.6978 | 1830 | 0.66978 | ThisIsExisting
577719 | RDC | Level: RDC | Core Face: Exterior | Level: R+1 | no | 0 | 3660 | 6.6978 | 1830 | 0.66978 | ThisIsExisting
577720 | RDC | Level: RDC | Core Face: Exterior | Level: R+1 | no | 0 | 3660 | 6.74655 | 1843.32 | 0.674655 | ThisIsExisting
577721 | RDC | Level: RDC | Core Face: Exterior | Level: R+1 | no | 0 | 3660 | 6.6978 | 1830 | 0.66978 | ThisIsExisting
577776 | RDC | Level: RDC | Core Face: Exterior | Level: R+1 | no | 0 | 3660 | 6.6978 | 1830 | 0.66978 | ThisIsExisting
577777 | RDC | Level: RDC | Core Face: Exterior | Level: R+1 | no | 0 | 3660 | 6.74655 | 1843.32 | 0.674655 | ThisIsExisting
577778 | RDC | Level: RDC | Core Face: Exterior | Level: R+1 | no | 0 | 3660 | 6.6978 | 1830 | 0.66978 | ThisIsExisting

# IfcWallStandardCase: Basic Wall:Wall-Int_200 (15)
In: R-1
Type - PredefinedType: STANDARD; Material: Plaster 12.5 mm, Concrete Masonry Units 175 mm, Plaster 12.5 mm
Type - Analytical Properties - Roughness: 3; Absorptance: 0.7; Heat Transfer Coefficient (U): 5.44559; Thermal Mass: 27.0794; Thermal Resistance (R): 0.183635
Type - Construction - Function: Interior; Wrapping at Inserts: Both; Width: 200 mm
Type - Graphics - Coarse Scale Fill Pattern: <Solid fill>; Coarse Scale Fill Color: 12632256
Type - Identity Data - Type Name: Wall-Int_200
Type - Materials and Finishes - Structural Material: Concrete Masonry Units
Type - Other - Category: Walls; Family Name: Basic Wall
Type - Pset_ElementShading - Roughness: 914.4 mm
Type - Pset_ProductRequirements - Category: Walls
Type - Pset_QuantityTakeOff - Reference: Wall-Int_200
Type - Pset_ReinforcementBarPitchOfWall - Reference: Wall-Int_200
Type - Pset_WallCommon - IsExternal: no; Reference: Wall-Int_200; ThermalTransmittance: 5.44559 kg/K/s3
Constraints - Base Constraint: Level: R-1; Base Extension Distance: 0 mm; Base is Attached: no; Base Offset: 0 mm; Cross-Section: Vertical; Related to Mass: no; Room Bounding: yes; Top Constraint: Level: RDC; Top Extension Distance: 0 mm; Top Offset: 0 mm; Unconnected Height: 3500 mm
Other - Family: Basic Wall: Wall-Int_200; Family and Type: Basic Wall: Wall-Int_200; Type: Basic Wall: Wall-Int_200; Type Id: Basic Wall: Wall-Int_200
Phasing - Phase Created: Existing
Structural - Enable Analytical Model: no; Structural: no; Structural Usage: Non-bearing
Pset_QuantityTakeOff - sets with these values: 2
Pset_WallCommon - LoadBearing: no
Name (Basic Wall:Wall-Int_200:...) | Top is Attached = ExtendToStructure | Location Line | Area (m2) | Length (mm) | Volume (m3) | ElementID
387178 | yes | Core Centerline | 15.4683 | 4770 | 3.09366 | 387178
387339 | no | Finish Face: Exterior | 15.9425 | 4645 | 3.1885 | 387339
387530 | yes | Core Centerline | 15.4683 | 4770 | 3.09366 | 387530
388163 | no | Core Face: Exterior | 15.82 | 4520 | 3.164 | 388163
388276 | no | Core Face: Exterior | 16.065 | 4770 | 3.213 | 388276
388346 | yes | Core Face: Exterior | 13.1177 | 4092.5 | 2.62354 | 388346
388430 | no | Core Face: Exterior | 34.93 | 10180 | 6.986 | 388430
388461 | no | Core Face: Exterior | 6.405 | 1930 | 1.281 | 388461
388504 | no | Core Face: Exterior | 34.8594 | 10380 | 6.97188 | 388504
389467 | yes | Core Centerline | 15.4683 | 4770 | 3.09366 | 389467
389468 | no | Finish Face: Exterior | 15.9425 | 4645 | 3.1885 | 389468
389470 | yes | Core Centerline | 15.4683 | 4770 | 3.09366 | 389470
389480 | no | Core Face: Exterior | 15.82 | 4520 | 3.164 | 389480
389481 | no | Core Face: Exterior | 16.065 | 4770 | 3.213 | 389481
389484 | no | Core Face: Exterior | 6.755 | 1930 | 1.351 | 389484

# IfcWindow: Entrance windows:Central, Entrance windows:Central:534478
In: RDC
Type - ParameterTakesPrecedence: no; Sizeable: no; Material: Stainless Steel, Brushed
Type - Analytical Properties(Type) - Analytic Construction: <None>; Define Thermal Properties by: Schematic Type
Type - Construction(Type) - Wall Closure: By host
Type - Dimensions(Type) - Height: 2340 mm; Width: 640 mm
Type - Identity Data(Type) - OmniClass Number: 23.30.20.00; OmniClass Title: Windows; Type Mark: 62; Type Name: Central
Type - Other(Type) - Category: Windows; Default Sill Height: 2 mm; Family Name: Entrance windows
Type - Pset_ProductRequirements - Category: Windows
Type - Pset_QuantityTakeOff - Reference: Central
Type - Pset_WindowCommon - IsExternal: no; Reference: Central
OverallHeight: 2340 mm; OverallWidth: 640 mm; Material: Stainless Steel, Brushed, Glass
Pset_OpeningElementCommon - Reference: Central; sets with these values: 2
Constraints - Level: Level: RDC; Sill Height: 2 mm
Dimensions - Area: 2.7635 m2; Volume: 0.0334496 m3
Identity Data - Comments: ThisIsExisting; Mark: 20
Other - Category: Windows; Family: Entrance windows: Central; Family and Type: Entrance windows: Central; Host Id: Basic Wall: Wall-Int 100; Type: Entrance windows: Central; Type Id: Entrance windows: Central; Head Height: 2342 mm
Phasing - Phase Created: Existing

# IfcWindow: Entrance windows:Door (6)
In: RDC
Type - ParameterTakesPrecedence: no; Sizeable: no; Material: Glass, Stainless Steel, Brushed
Type - Analytical Properties - Define Thermal Properties by: Schematic Type; Analytic Construction: <None>
Type - Construction - Wall Closure: By host
Type - Dimensions - Height: 2800 mm; Width: 1250 mm
Type - Identity Data - OmniClass Number: 23.30.20.00; OmniClass Title: Windows; Type Mark: 61; Type Name: Door
Type - Other - Category: Windows; Default Sill Height: 2 mm; Family Name: Entrance windows
Type - Pset_ProductRequirements - Category: Windows
Type - Pset_QuantityTakeOff - Reference: Door
Type - Pset_WindowCommon - IsExternal: no; Reference: Door
OverallHeight: 2800 mm; OverallWidth: 1250 mm
Constraints - Level: Level: RDC; Sill Height: 2 mm
Dimensions - Area: 6.68056 m2; Volume: 0.05488 m3
Identity Data - Comments: ThisIsExisting
Other - Host Id: Basic Wall: Wall-Int 100; Family: Entrance windows: Door; Family and Type: Entrance windows: Door; Head Height: 2802 mm; Type: Entrance windows: Door; Type Id: Entrance windows: Door
Phasing - Phase Created: Existing
Name (Entrance windows:Door:...) | Mark
531310 | 7
531570 | 8
531658 | 9
533483 | 17
533484 | 18
533485 | 19

# IfcWindow: Entrance windows:Entrance windows (2)
In: RDC
Type - ParameterTakesPrecedence: no; Sizeable: no; Material: Glass, Stainless Steel, Brushed
Type - Analytical Properties - Define Thermal Properties by: Schematic Type; Analytic Construction: <None>
Type - Construction - Wall Closure: By host
Type - Dimensions - Height: 2800 mm; Width: 3700 mm
Type - Identity Data - OmniClass Number: 23.30.20.00; OmniClass Title: Windows; Type Mark: 58; Type Name: Entrance windows
Type - Other - Category: Windows; Default Sill Height: 2 mm; Family Name: Entrance windows
Type - Pset_ProductRequirements - Category: Windows
Type - Pset_QuantityTakeOff - Reference: Entrance windows
Type - Pset_WindowCommon - IsExternal: no; Reference: Entrance windows
OverallHeight: 2800 mm; OverallWidth: 3700 mm
Constraints - Level: Level: RDC; Sill Height: 2 mm
Dimensions - Area: 20.1997 m2; Volume: 0.1176 m3
Identity Data - Comments: ThisIsExisting
Other - Host Id: Basic Wall: Wall-Int 100; Family: Entrance windows: Entrance windows; Family and Type: Entrance windows: Entrance windows; Head Height: 2802 mm; Type: Entrance windows: Entrance windows; Type Id: Entrance windows: Entrance windows
Phasing - Phase Created: Existing
Name (Entrance windows:Entrance windows:...) | Mark
527844 | 5
533481 | 15

# IfcWindow: Entrance windows:Short (2)
In: RDC
Type - ParameterTakesPrecedence: no; Sizeable: no; Material: Glass, Stainless Steel, Brushed
Type - Analytical Properties - Define Thermal Properties by: Schematic Type; Analytic Construction: <None>
Type - Construction - Wall Closure: By host
Type - Dimensions - Height: 2800 mm; Width: 2200 mm
Type - Identity Data - OmniClass Number: 23.30.20.00; OmniClass Title: Windows; Type Mark: 60; Type Name: Short
Type - Other - Category: Windows; Default Sill Height: 2 mm; Family Name: Entrance windows
Type - Pset_ProductRequirements - Category: Windows
Type - Pset_QuantityTakeOff - Reference: Short
Type - Pset_WindowCommon - IsExternal: no; Reference: Short
OverallHeight: 2800 mm; OverallWidth: 2200 mm
Constraints - Level: Level: RDC; Sill Height: 2 mm
Dimensions - Area: 11.9227 m2; Volume: 0.0792 m3
Identity Data - Comments: ThisIsExisting
Other - Host Id: Basic Wall: Wall-Int 100; Family: Entrance windows: Short; Family and Type: Entrance windows: Short; Head Height: 2802 mm; Type: Entrance windows: Short; Type Id: Entrance windows: Short
Phasing - Phase Created: Existing
Name (Entrance windows:Short:...) | Mark
530175 | 6
533482 | 16
